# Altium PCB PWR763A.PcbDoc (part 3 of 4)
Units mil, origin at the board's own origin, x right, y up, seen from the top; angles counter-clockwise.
Board outline 5000 x 7000 mil, 4 copper layers (Top Layer, Signal Layer 1, Signal Layer 2, Bottom Layer), stack 61.2 mil thick; 559 components, 281 nets, 1477 pads, 685 vias.

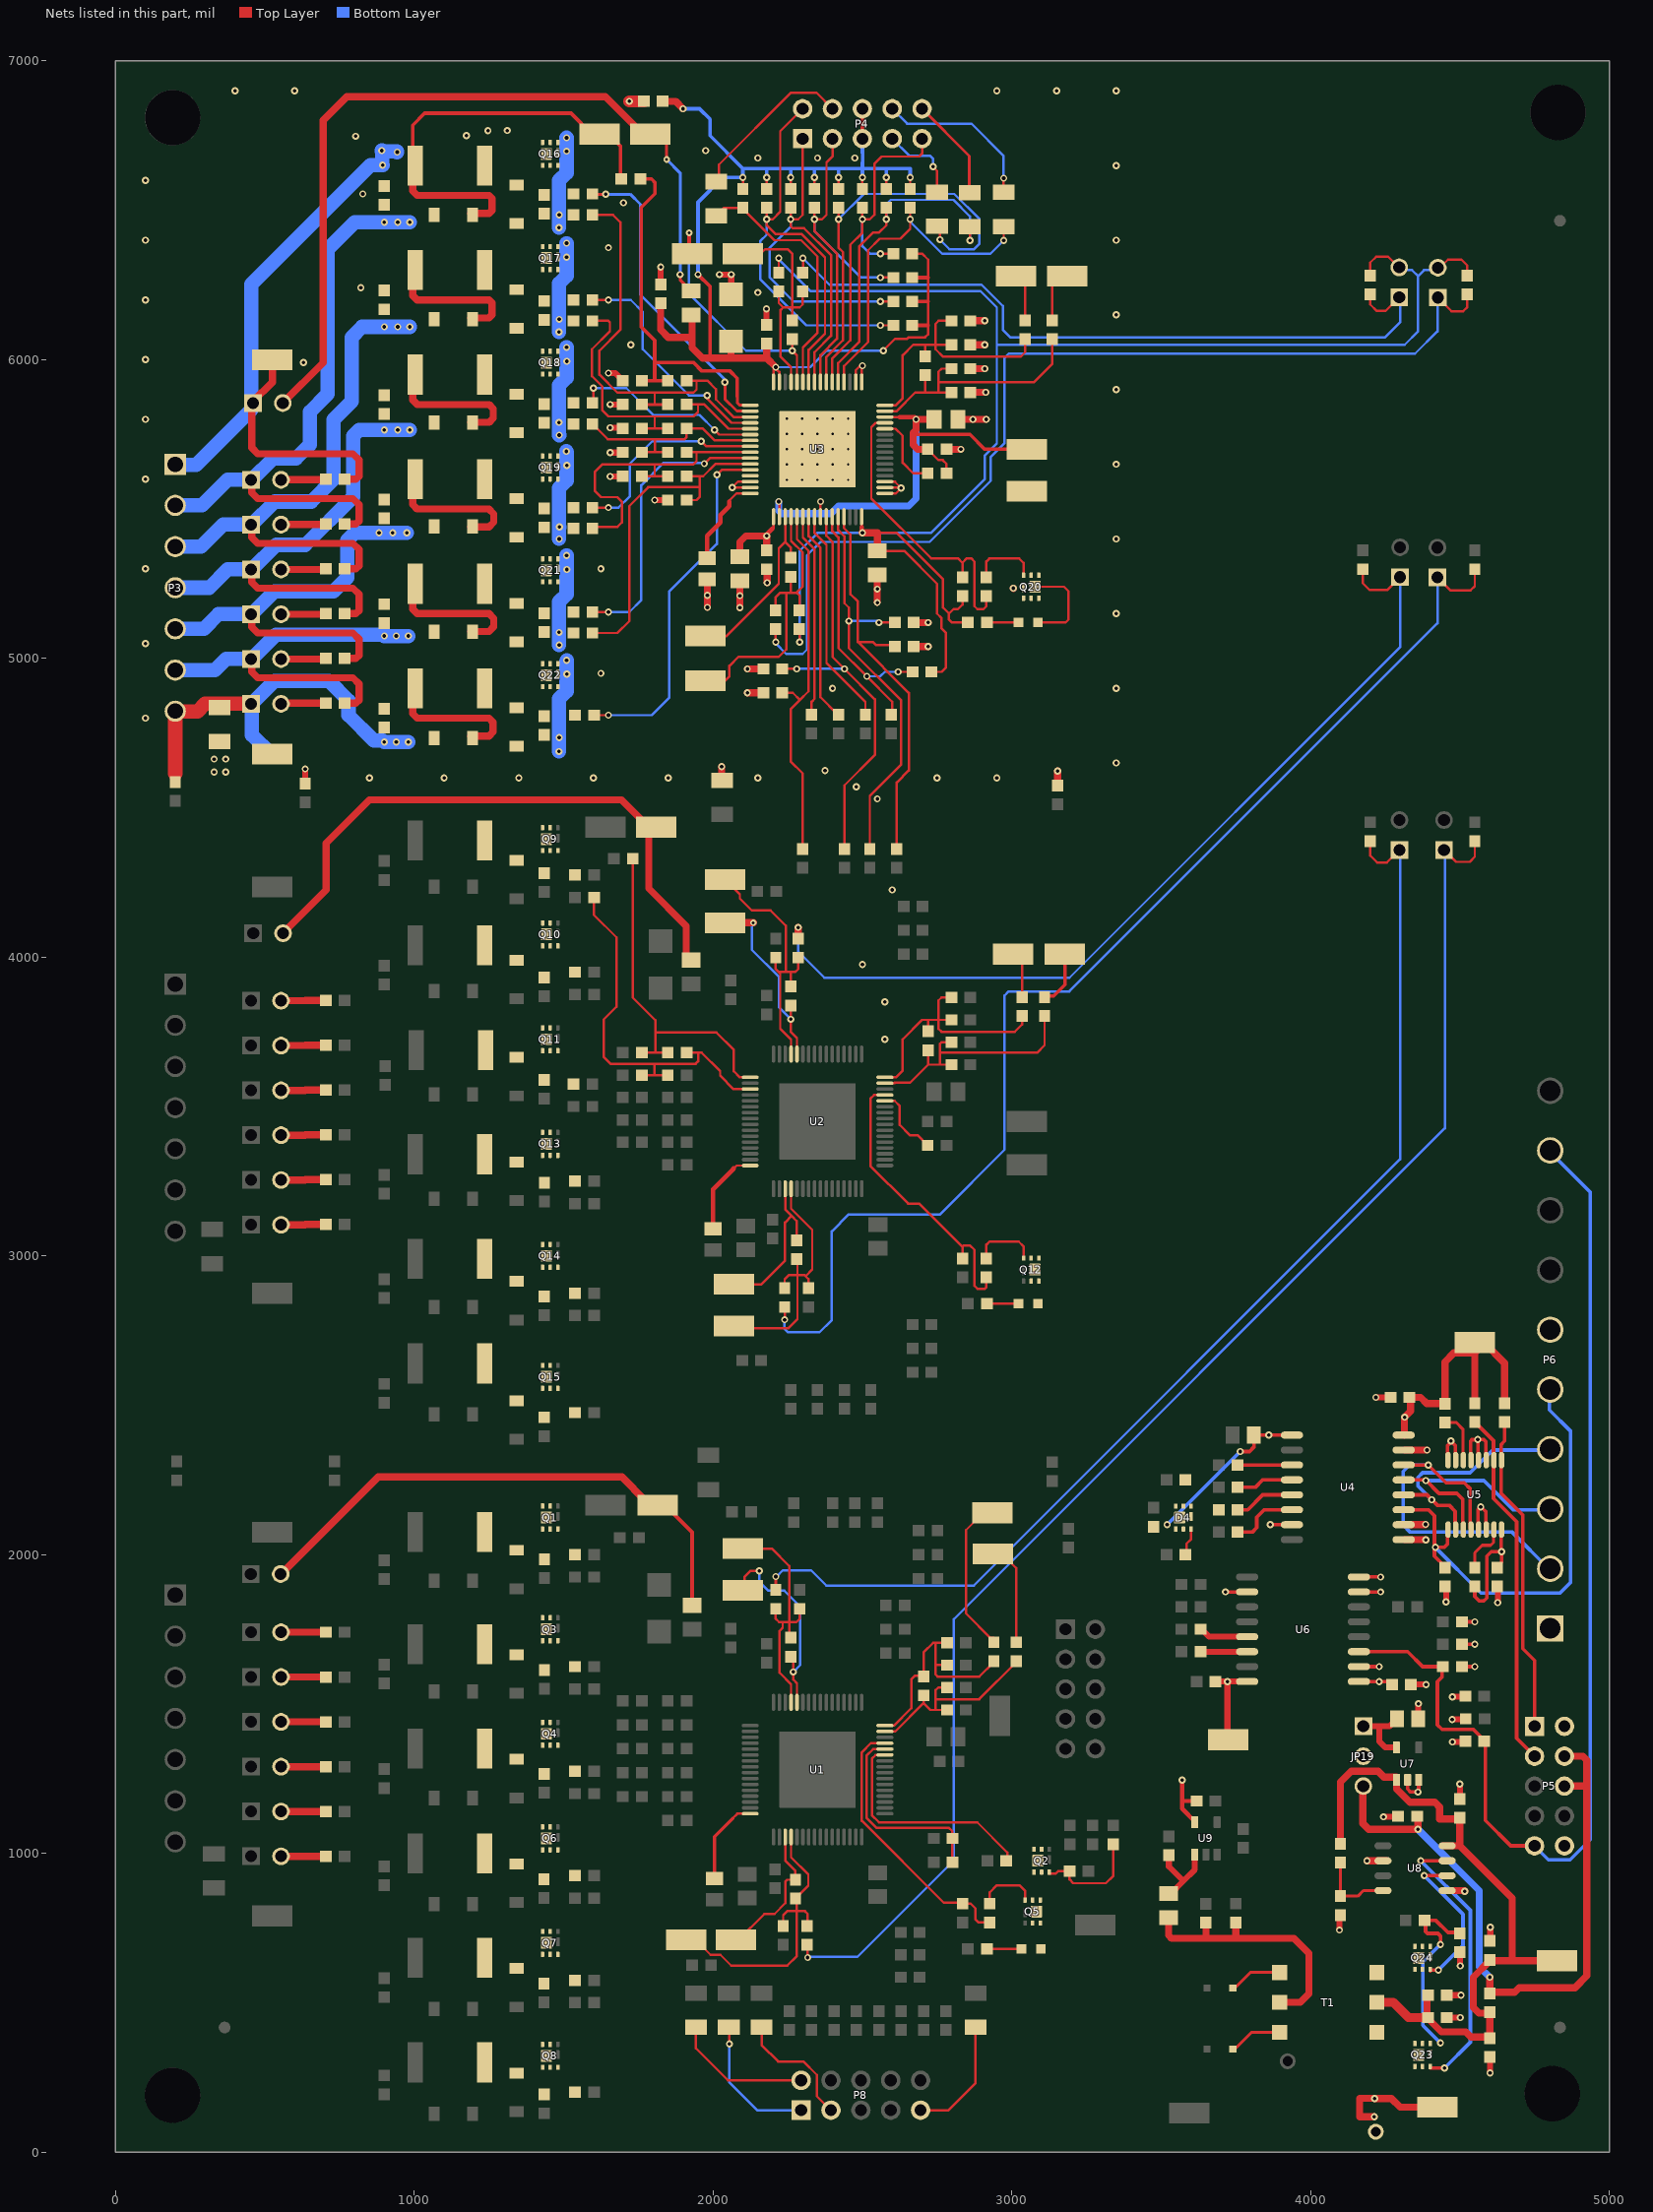
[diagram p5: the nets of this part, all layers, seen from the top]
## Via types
v1: diameter 24, hole 12, Top Layer to Bottom Layer, tented both sides, 607 vias
v2: diameter 19.68, hole 7.87, Top Layer to Bottom Layer, 75 vias
v3: diameter 22, hole 10, Top Layer to Bottom Layer, tented both sides, 3 vias

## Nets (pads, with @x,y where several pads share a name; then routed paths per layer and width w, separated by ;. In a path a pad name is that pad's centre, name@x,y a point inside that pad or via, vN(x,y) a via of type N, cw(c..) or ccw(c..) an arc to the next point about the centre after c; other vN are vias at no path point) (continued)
2-VC5: C49.2 C52.1 C53.1 R118.1 U2.3 | length 1338.8
  Top Layer w8: R118.1@1601.5,4200 1601.5,4141.5 1677,4066 1677,3834.04 1634,3791.04 1634,3666 1656.79,3643.21 1804,3643.21 ; C52.1@1761.5,3605 1803,3605 ; C53.1@1848.5,3605 1803,3605 ; C49.2@1911.5,3680 1950.22,3680 ; U2.3@2124.61,3558.27 2068.91,3558.27 2023.94,3603.24 2023.94,3618.28 1962.22,3680 1950.22,3680 ; 1803,3605 1804,3606 1804,3643.21 ; 1804,3643.21 1942.17,3643.21 1950.22,3651.26 1950.22,3680
2-VC6: C48.1 C49.1 R114.1 U2.1 | length 1190.1
  Top Layer w8: R114.1@1731.5,4330 1731.5,3864.5 1807,3789 1807,3746.91 ; C48.1@1761.5,3680 1807,3680 ; C49.1@1848.5,3680 1807,3680 ; U2.1@2124.61,3597.64 2090.36,3597.64 2070,3618 2070,3689 2011.1,3747.9 1807.99,3747.9 1807,3746.91 ; 1807,3680 1807,3746.91
3-ALERT_N: C2.2 P4.1 R4.1 U3.57 | length 1646
  Top Layer w8: R4.1@2260,6505 v1(2260,6470) ; P4.1@2300,6740 2300,6485 2285,6470 v1(2260,6470) ; U3.57@2340.16,5928.35 2340.16,5969.84 2340,5970 2340,6025 2395,6080 2395,6350 2305,6440 2267,6440 2260,6447 v1(2260,6470) ; v1(2560,6195) C2.2@2600,6195
  Bottom Layer w8: v1(2260,6470) 2260,6445 2190,6375 2190,6275 2270,6195 v1(2560,6195)
3-ALERT_S: R21.2 U3.23 | length 700.8
  Top Layer w8: U3.23@2320.47,5471.65 2320.47,5409.53 2360,5370 2360,4870 2415,4815 R21.2@2420,4815
3-CB1: R186.1 U3.12 | length 1207.1
  Top Layer w8: R186.1@1601.5,4810 v1(1650,4810) ; v1(2013,5615) 2029.1,5631.1 U3.12@2124.61,5631.1
  Bottom Layer w8: v1(1650,4810) 1795,4810 1853,4868 1853,5223 2013,5383 v1(2013,5615)
3-CB2: R178.1 U3.10 | length 967.4
  Top Layer w8: R178.1@1596.5,5155 v1(1650,5155) ; v1(1971,5652) 1989.47,5670.47 U3.10@2124.61,5670.47
  Bottom Layer w8: v1(1650,5155) 1720,5155 1760,5195 1760,5580 1835,5655 v1@1970,5655
3-CB3: R173.1 U3.8 | length 691
  Top Layer w8: R173.1@1596.5,5505 v1(1650,5505) ; v1(1961,5727) 1978.16,5709.84 U3.8@2124.61,5709.84
  Bottom Layer w8: v1(1650,5505) 1684,5505 1721,5542 1721,5651 1797,5727 v1(1961,5727)
3-CB4: R162.1 U3.6 | length 640.6
  Top Layer w8: R162.1@1596.5,5855 1600,5858.5 v1(1600,5905) ; v1(2005,5765) 2020.79,5749.21 U3.6@2124.61,5749.21
  Bottom Layer w8: v1(1600,5905) 1710,5905 1800,5815 1955,5815 v1(2005,5765)
3-CB5: R157.1 U3.4 | length 770.6
  Top Layer w8: R157.1@1600,6200 v1(1650,6200) ; v1(1980,5880) 1980,5871 2062.42,5788.58 U3.4@2121.65,5788.58
  Bottom Layer w8: v1(1650,6200) 1725,6200 1765,6160 1765,6035 1920,5880 v1(1980,5880)
3-CB6: R153.1 U3.2 | length 1045.4
  Top Layer w10: R153.1@1596.5,6555 1597.5,6554 v1(1641,6554) ; v1(2040,5925) 2040,5868 2080.05,5827.95 U3.2@2124.61,5827.95
  Bottom Layer w10: v1(1641,6554) 1723,6554 1757,6520 1757,6217 2040,5934 v1(2040,5925)
3-CELL1: C103.2 C113.1 JP5.1 P3.6 Q21.4 Q21.7 R18.2 R180.1 R182.2 R183.2 Z36.2 Z37.2 Z38.1 | length 2142.3
  Top Layer w24: JP5.1@456,4998 456,4955 476,4935 795,4935 815,4915 815,4860 805,4850 R18.2@770,4850 ; R183.2@995,4900 995,4815 1010,4800 1250,4800 1263.94,4786.06 1263.94,4753.94 1250,4740 Z38.1@1189.5,4740
  Bottom Layer w48: P3.6@200,4961.02 333.02,4961.02 370,4998 456,4998 537,5079 896,5079 v1(900,5075) v1(940,5075) v1(980,5075) ; v1(1485,5045) 1485,5085 v1(1484.88,5087.01) 1485,5087.01 1485,5190 1510,5215 1510,5297.49 v1(1510.31,5297.49) 1510,5305 v1(1510,5345)
3-CELL2: C100.2 C103.1 JP4.1 P3.5 Q19.4 Q19.7 R17.2 R174.1 R175.2 R176.2 Z34.2 Z35.2 Z36.1 | length 2292.6
  Top Layer w8: v1(1509.17,5693.1) 1509.57,5691.11 1509.77,5691.15 v1@1510,5690
  Top Layer w24: JP4.1@456,5148 456,5105 476,5085 795,5085 815,5065 815,5010 805,5000 R17.2@770,5000 ; R176.2@995,5250 995,5165 1010,5150 1250,5150 1265.73,5134.27 1265.73,5105.73 1250,5090 Z36.1@1189.5,5090
  Bottom Layer w48: P3.5@200,5098.81 295.82,5098.82 345,5148 456,5148 532,5224 730,5224 776,5270 776,5395 801,5420 v1(882,5420) v1(928,5420) v1(975,5420) ; v1(1485,5400) 1485,5435 v1(1486,5440) 1485,5440 1485,5570 1510,5595 1510,5646.51 v1(1510.58,5646.51) 1510,5651 1510,5690 1509.77,5691.15 1509.57,5691.11 v1(1509.17,5693.1)
3-CELL3: C95.2 C100.1 JP3.1 P3.4 Q18.4 Q18.7 R16.2 R163.1 R164.2 R167.2 Z32.2 Z33.2 Z34.1 | length 2432.5
  Top Layer w24: JP3.1@456,5298 456,5255 476,5235 795,5235 815,5215 815,5160 805,5150 R16.2@770,5150 ; R167.2@995,5600 995,5515 1010,5500 1250,5500 1266.09,5483.91 1266.09,5456.09 1250,5440 Z34.1@1189.5,5440
  Bottom Layer w48: P3.4@200,5236.61 313.61,5236.61 375,5298 456,5298 538,5380 635,5380 795,5540 795,5745 815,5765 v1(900,5765) v1(945,5765) v1(985,5765) ; v1(1485.17,5747.45) 1485,5750 1485,5785 v1(1484,5790) 1485,5790 1485,5915 1510,5940 1510,5994.7 v1(1510.65,5994.7) 1510,6000 1510,6040 v1(1509.91,6041.1)
3-CELL4: C92.2 C95.1 JP2.1 P3.3 Q17.4 Q17.7 R15.2 R158.1 R159.2 R160.2 Z30.2 Z31.2 Z32.1 | length 2642.7
  Top Layer w24: JP2.1@456,5448 456,5405 476,5385 795,5385 815,5365 815,5310 805,5300 R15.2@770,5300 ; R160.2@995,5950 995,5865 1010,5850 1250,5850 1264.66,5835.34 1264.66,5804.66 1250,5790 Z32.1@1189.5,5790
  Bottom Layer w48: P3.3@200,5374.41 286.41,5374.41 360,5448 456,5448 533,5525 655,5525 730,5600 730,5800 790,5860 790,6075 825,6110 v1(900,6110) v1(945,6110) v1(985,6110) ; v1(1484.47,6092.3) 1485,6095 v1(1485,6135) 1485,6255 1510,6280 1510,6342.93 v1(1509.8,6342.93) 1510,6350 v1(1510,6390)
3-CELL5: C89.2 C92.1 JP1.1 P3.2 Q16.4 Q16.7 R14.2 R154.1 R155.2 R156.2 Z28.2 Z29.2 Z30.1 | length 2835.3
  Top Layer w24: JP1.1@456,5598 456,5555 476,5535 795,5535 815,5515 815,5460 805,5450 R14.2@770,5450 ; R156.2@995,6300 995,6215 1010,6200 1250,6200 1260,6190 1260,6150 1250,6140 Z30.1@1189.5,6140
  Bottom Layer w48: P3.2@200,5512.2 200.8,5513 290,5513 375,5598 456,5598 528,5670 605,5670 650,5715 650,5825 710,5885 710,6370 800,6460 v1(900,6460) v1(945,6460) v1(985,6460) ; v1(1484.6,6441.83) 1485,6445 v1(1485,6485) 1485,6600 1510,6625 1510,6697.97 v1(1509.87,6697.97) 1510,6700 1510,6740 v1(1510.04,6742.79)
3-CELL6: C89.1 J7.1 P3.1 R13.2 R150.2 R151.2 TP1.1 TP-C5.1 Z28.1 | length 3734.5
  Top Layer w12: R150.2@995,6650 995,6785 1035,6825 1525,6825 1595,6755 1650,6755 1690,6715 R151.2@1690,6608.5
  Top Layer w24: J7.1@455,5850 456,5850 456,5705 476,5685 795,5685 815,5665 815,5610 805,5600 R13.2@770,5600 ; J7.1@460,5855 460,5860 525,5925 TP1.1@525,6000 ; R150.2@995,6650 995,6565 1010,6550 1250,6550 1260,6540 1260,6500 1250,6490 Z28.1@1189.5,6490
  Bottom Layer w48: P3.1@200,5650 202,5648 270,5648 455,5833 455,6252 854,6651 v1@892.5,6651 ; v1(894,6651) v1@892.5,6651 ; v1(943,6695) 943,6697.5 v1@892.5,6697.5 ; v1@892.5,6651 v1@892.5,6697.5 ; v1@892.5,6697.5 892.5,6700 v1(891,6700) 891,6697.5 v1@892.5,6697.5
3-CONV_N: R1.1 R2.1 U3.59 | length 853.3
  Top Layer w8: R1.1@2011,6481.91 2037.59,6508.5 R2.1@2100,6508.5 ; R2.1@2100,6505 2205,6400 2295,6400 2350,6345 2350,6090 2300.79,6040.79 U3.59@2300.79,5928.35
3-CONV_S: C111.1 R25.2 U3.21 | length 1233.6
  Top Layer w8: C111.1@2231.5,4885 2267,4885 2291,4861 ; U3.21@2281.1,5471.65 2281.1,5398.9 2320,5360 2320,4890 2291,4861 ; R25.2@2300,4365 2300,4615.17 2260,4655.17 2260,4830 2291,4861
3-CS_N: R9.1 R12.1 U3.52 | length 1146.9
  Top Layer w8: U3.52@2438.58,5928.35 2438.58,5978.58 2519,6059 2519,6366 2558,6405 2627,6405 2660,6438 v1(2660,6470) R9.1@2660,6505 ; R12.1@2958.87,6446.72 2973.24,6432.35 v1(2973.24,6399.38)
  Bottom Layer w8: v1(2660,6470) 2660,6462 2768,6354 2927.86,6354 v1(2973.24,6399.38)
3-CS_S: C110.1 R28.2 U3.29 | length 1339.5
  Top Layer w8: U3.29@2438.58,5471.65 2438.58,5436.42 2460,5415 2460,5215 2485,5190 2485,5055 ; C110.1@2605,5040 2600,5045 2545,5045 2535,5055 2485,5055 ; R28.2@2615,4365 2615,4584.43 2655.57,4625 2655.57,4884.43 2485,5055
3-DRDY_N: C1.2 P4.2 R3.1 U3.58 | length 1877.6
  Top Layer w8: R3.1@2180,6505 v1(2180,6470) ; P4.2@2300,6840 2225,6765 2225,6495 2200,6470 v1(2180,6470) ; U3.58@2320.47,5928.35 2320.47,6032.97 2375,6087.5 2375,6342.63 2297.63,6420 2210,6420 2180,6450 v1(2180,6470) ; v1(2560,6115) C1.2@2600,6115
  Bottom Layer w8: v1(2180,6470) 2180,6418.81 2159,6397.81 2159,6268.37 2312.37,6115 v1(2560,6115)
3-DRDY_S: R24.2 U3.22 | length 677
  Top Layer w8: U3.22@2300.79,5471.65 2300.79,5404.21 2340,5365 2340,4865 2330,4855 R24.2@2330,4815
3-FAULT_N: C3.2 P4.3 R5.1 U3.56 | length 1304.3
  Top Layer w8: R5.1@2340,6505 v1(2340,6470) ; U3.56@2359.84,5928.35 2359.84,6014.84 2415,6070 2415,6355 2340,6430 v1(2340,6470) ; P4.3@2400,6740 2400,6680 2380,6660 2380,6485 2365,6470 v1(2340,6470) ; v1(2560,6275) C3.2@2600,6275
  Bottom Layer w8: v1(2340,6470) 2340,6430 2495,6275 v1(2560,6275)
3-FAULT_S: R22.2 U3.24 | length 727
  Top Layer w8: U3.24@2340.16,5471.65 2340.16,5419.84 2380,5380 2380,4985 2510,4855 R22.2@2510,4815
3-LDOA: C116.1 C117.1 U3.17 | length 260.9
  Top Layer w8: 2202.36,5437.36 U3.17@2202.36,5471.65
  Top Layer w15: v1(2180,5410) 2180,5415 2200,5435
  Top Layer w24: C117.1@2090,5340 2090,5390 2110,5410 v1(2180,5410) C116.1@2180,5365
3-LDOD1: C118.1 C119.1 R172.2 TP-VPROG3.1 U3.18 U3.46 | length 1655.8
  Top Layer w8: v1(2220,5525) 2222.05,5522.95 U3.18@2222.05,5471.65 ; U3.46@2578.35,5808.27 2625,5808.27 ; C118.1@2718.5,5700 2754.85,5663.65 2768.96,5663.65 2781.5,5651.11 R172.2@2781.5,5620
  Top Layer w12: 2670,5750 2860,5750 2910,5700 TP-VPROG3.1@3050,5700
  Top Layer w15: 2625,5808.27 2675,5808.27 v1(2680,5800)
  Top Layer w24: C118.1@2715,5700 2685,5700 2670,5715 2670,5750 2670,5755 2680,5765 v1(2680,5800) C119.1@2740,5800
  Bottom Layer w24: v1(2220,5525) 2220,5495 2230,5485 2395,5485 2420,5510 2655,5510 2680,5535 v1(2680,5800)
3-REG50: C96.1 C97.1 C115.1 J8.2 J9.2 R161.2 R168.2 R177.1 RT5.2 RT6.2 U3.32 | length 5938.3
  Top Layer w8: C97.1@2220,6291.5 v1(2220,6340) ; v1(2290,5055) C96.1@2290,5095 ; 2497.64,5440 U3.32@2497.64,5471.65 ; C115.1@2550,5360 2640,5360 2750,5250 2750,5150 2765,5135 2765,5100 2780,5085 2780,4970 2765,4955 R177.1@2735,4955 ; 2550,5420 2615,5420 2770,5265 2770,5170 2790,5150 ; R168.2@2835,5205 2835,5180 2820,5165 2805,5165 2790,5150 ; R161.2@2850,5120 2800,5120 2790,5130 2790,5150 ; RT6.2@4200,6270 4200,6325 4220,6345 4260,6345 4300,6305 J9.2@4300,6300 ; J8.2@4425,6300 4460,6335 4505,6335 4525,6315 RT5.2@4525,6270
  Top Layer w15: 2497.64,5440 2497.64,5422.36 v1(2500,5420)
  Top Layer w25: v1(2500,5420) 2550,5420 C115.1@2550,5360
  Bottom Layer w8: v1(2220,6340) 2220,6336 2326,6230 2895,6230 2950,6175 2950,6050 ; v1(2290,5055) 2290,5360 2350,5420 2728.94,5420 2910,5601.06 2910,5680 2950,5720 2950,6050 ; J9.2@4300,6300 4340,6300 4360,6280 ; J8.2@4425,6300 4380,6300 4360,6280 ; 2950,6050 4315,6050 4360,6095 4360,6280
3-SCLK_N: R6.1 R10.1 U3.55 | length 1435.9
  Top Layer w8: U3.55@2379.53,5925.39 2379.53,6009.53 2435,6065 2435,6360 2420,6375 v1(2420,6470) R6.1@2420,6505 ; R10.1@2750,6446.91 2760,6436.91 v1(2760,6402)
  Bottom Layer w8: v1(2420,6470) 2505,6555 2807.63,6555 2892,6470.63 2892,6388 2874,6370 2791,6370 2760,6401 v1(2760,6402)
3-SCLK_S: C108.1 R26.2 U3.26 | length 1421.2
  Top Layer w8: C108.1@2235,4965 v1(2280,4965) ; U3.26@2379.53,5471.65 2379.53,5410.47 2400,5390 2400,5005 v1(2440,4965) 2542,4863 2542,4677 2440,4575 R26.2@2440,4365
  Bottom Layer w8: v1(2280,4965) v1(2440,4965)
3-SDI_N: R8.1 R11.1 U3.53 | length 1141.6
  Top Layer w8: U3.53@2418.9,5928.35 2418.9,5988.9 2490,6060 2490,6380 2535,6425 2555,6425 2580,6450 v1(2580,6470) R8.1@2580,6505 ; v1(2860,6399) R11.1@2860,6445.54
  Bottom Layer w8: v1(2580,6470) 2580,6520 2595,6535 2805,6535 2860,6480 v1(2860,6399)
3-SDI_S: C109.1 R27.2 U3.28 | length 1389.7
  Top Layer w8: U3.28@2418.9,5471.65 2418.9,5429.36 2440,5408.26 2440,5185 2455,5170 v1(2455,5125) 2455,5033.94 2630,4858.94 2630,4645 2525,4540 R27.2@2525,4365 ; v1(2555,5120) C109.1@2605,5120
  Bottom Layer w8: v1(2455,5125) 2550,5125 v1(2555,5120)
3-SDO_N: C5.2 P4.9 R7.1 U3.54 | length 1259.5
  Top Layer w8: U3.54@2399.21,5928.35 2399.21,6004.21 2460,6065 2460,6385 2500,6425 v1(2500,6470) ; R7.1@2500,6505 v1(2500,6470) ; v1(2560,6355) C5.2@2600,6355 ; P4.9@2700,6740 2700,6690 2690,6680 2565,6680 2540,6655 2540,6485 2525,6470 v1(2500,6470)
  Bottom Layer w8: v1(2500,6470) 2500,6380 2525,6355 v1(2560,6355)
3-SDO_S: R23.2 R177.2 U3.27 | length 896
  Top Layer w8: U3.27@2399.21,5471.65 2399.21,5425.79 2420,5405 2420,5035 v1(2515,4940) 2600,4855 R23.2@2600,4815 ; v1(2620,4955) R177.2@2665,4955
  Bottom Layer w8: v1(2515,4940) 2560,4940 2575,4955 v1(2620,4955)
3-VBAT: C1.1 C2.1 C3.1 C4.1 C5.1 C88.1 C114.1 P4.5 P4.6 R2.2 R3.2 R4.2 R5.2 R6.2 R7.2 R8.2 R9.2 R152.2 U3.63 U3.64 Z27.2 | length 4241.1
  Top Layer w8: R2.2@2100,6575 v1(2100,6610) ; R3.2@2180,6575 v1(2180,6610) ; U3.64@2202.36,5928.35 2202.36,5967.36 v1@2207.91,5972.91 ; v1(2210,5975) v1@2207.91,5972.91 ; U3.63@2222.05,5928.35 2222.05,5958.76 v1@2207.91,5972.91 ; R4.2@2260,6575 v1(2260,6610) ; R5.2@2340,6575 v1(2340,6610) ; R6.2@2420,6575 v1(2420,6610) ; R7.2@2500,6575 v1(2500,6610) ; v1(2570,6030) 2610,6070 2650,6070 2655,6075 2710,6075 2720,6085 2720,6115 2720,6195 2720,6275 2720,6335 2700,6355 C5.1@2670,6355 ; R8.2@2580,6575 v1(2580,6610) ; R9.2@2660,6575 v1(2660,6610)
  Top Layer w12: v1(1950,6285) 1990,6245 1990,6005 ; P4.5@2500,6740 P4.6@2500,6840 ; C1.1@2670,6115 2720,6115 ; C2.1@2670,6195 2720,6195 ; C3.1@2670,6275 2720,6275
  Top Layer w24: C114.1@1825,6185 1825,6100 1850,6075 1930,6075 ; C88.1@1835,6865 1875,6865 v1(1900,6840) ; R152.2@1930,6155 1930,6075 ; Z27.2@2060,6070.5 2060,6005 ; C4.1@2180,6050 2180,6005 ; v1(2210,5975) 2180,6005 ; 1930,6075 1930,6040 1965,6005 1990,6005 2060,6005 ; 2060,6005 2180,6005
  Bottom Layer w8: v1(2210,5975) 2325,5975 2380,6030 v1(2570,6030)
  Bottom Layer w12: v1(1900,6840) 1955,6840 1990,6805 1990,6750 2100,6640 ; v1(1950,6285) 1950,6527.09 2032.91,6610 v1(2100,6610) 2100,6640 ; v1(2180,6610) 2180,6640 ; v1(2260,6610) 2260,6640 ; v1(2340,6610) 2340,6640 ; v1(2420,6610) 2420,6640 ; v1(2500,6610) 2500,6640 ; P4.5@2500,6740 2500,6692.13 2501,6691.13 2501,6660.62 2500,6659.62 2500,6640 ; v1(2580,6610) 2580,6640 ; v1(2660,6610) 2660,6640 2580,6640 ; 2100,6640 2180,6640 ; 2180,6640 2260,6640 ; 2260,6640 2340,6640 ; 2340,6640 2420,6640 ; 2420,6640 2500,6640 ; 2500,6640 2580,6640
3-VC0: C4.2 C6.2 C7.1 C86.2 C88.2 C90.2 C93.2 C98.2 C101.2 C104.2 C105.2 C107.2 C108.2 C109.2 C110.2 C111.2 C112.2 C113.2 C114.2 C115.2 C116.2 C117.2 C118.2 C119.2 JP6.1 P3.7 Q20.4 Q20.7 Q22.4 Q22.7 R19.1 R19.2 R20.2 R29.2 R181.2 R185.2 R187.1 TP2.1 TP-VSS2.1 U3.13 U3.14 U3.15 U3.25 U3.33 U3.34 U3.35 U3.49 U3.50 U3.65 Z27.1 Z38.2 Z39.2 | length 3647.8
  Top Layer w8: v1(2064,5572) v1(2064,5572) ; U3.15@2121.65,5572.05 v1(2064,5572) ; U3.14@2121.65,5591.73 2083.73,5591.73 v1(2064,5572) ; U3.25@2359.84,5471.65 2359.84,5524.84 v1(2360,5525) ; U3.50@2477.95,5928.35 2477.95,5965 2492.95,5980 v1(2500,5980) 2497.64,5977.64 U3.49@2497.64,5928.35 ; U3.33@2578.35,5552.36 2612.36,5552.36 v1(2630,5570) v1@2627.95,5572.05 ; U3.34@2578.35,5572.05 v1@2627.95,5572.05 ; U3.35@2578.35,5591.73 2610,5591.73 2610,5590 v1@2627.95,5572.05
  Top Layer w20: R20.2@200,4590 200,4615 ; C6.2@635,4581.5 v1(635,4630) ; v1(1650,5955) 1673.5,5955 C86.2@1698.5,5930 ; v1(1656,5609) C101.2@1698.5,5609 ; v1(1656,5689) C98.2@1698.5,5689 ; v1(1656,5772) C93.2@1698.5,5772 ; v1(1656,5850) C90.2@1698.5,5850 ; v1(1805,5530) C107.2@1848.5,5530 ; C114.2@1825,6251.5 v1(1825,6310) ; v1(2022,6285) v1(2061,6285) 2061,6219.74 Z27.1@2060,6218.74 ; v1(2179,6170) 2179,6117.5 C4.2@2180,6116.5
  Top Layer w24: v1(1981,5171) v1(1981,5211) C112.2@1981,5261 ; R29.2@2029,4593 v1(2029,4638) ; v1(2090,5170) v1(2090,5210) C117.2@2090,5260 ; v1(2115,4885) C111.2@2165,4885 ; v1(2115,4965) C108.2@2165,4965 ; v1(2181,5253) C116.2@2181,5298 ; v1(2550,5187) v1(2550,5232) C115.2@2550,5277 ; C110.2@2675,5040 v1(2720,5040) ; C109.2@2675,5120 v1(2720,5120) ; C118.2@2785,5700 v1(2830,5700) ; C119.2@2820,5800 v1(2870,5800) v1(2915,5800) ; R185.2@2865,5970 v1(2910,5970) ; R181.2@2865,6050 v1(2910,6050) ; C105.2@2865,6131 v1(2910,6131) ; C104.2@2868,5891 v1(2913,5891) ; v1(3005,5235) v1@3005.91,5234.09 ; C7.1@3154,4578 v1(3154,4623)
  Top Layer w40: v1(1720,6865) C88.2@1768.5,6865
  Top Layer w48: 200,4615 P3.7@200,4823 ; P3.7@200,4823.22 P3.7@200,4823 ; JP6.1@456,4848 350,4848 300,4848 275,4823 P3.7@200,4823
  Bottom Layer w48: 520,4680 456,4744 456,4848 532,4924 715,4924 780,4859 780,4810 865,4725 895,4725 v1(900,4720) v1(940,4720) v1(980,4720) ; v1(1484.22,4688.31) 1485,4695 v1(1485,4735) 1485,4865 1510,4890 1510,4947.07 v1(1510.48,4947.07) 1510,4950 1510,4990 v1(1510.07,4994.07)
  other v1: 2575,3725 2575,3850 2500,3975 2600,4225 2550,4530 2480,4570 850,4600 1100,4600 1350,4600 1600,4600 1850,4600 2150,4600 2750,4600 2950,4600 330,4620 369,4620 2375,4625 3350,4650 330,4663 369,4663 100,4800 2400,4900 3350,4900 1625,4950 100,5050 3350,5150 100,5300 1625,5300 3350,5400 100,5600 3350,5650 100,5800 3350,5900 629,5991 100,6000 1725,6050 3350,6150 100,6200 2150,6225 821,6241 1650,6375 100,6400 3350,6400 1700,6525 828,6555 100,6600 3350,6650 2150,6675 2350,6675 2475,6675 1975,6700 804,6748 1175,6750 1246.62,6766.94 1311.64,6767.13 400,6900 600,6900 2950,6900 3150,6900 3350,6900
  other v2: 2247.64,5597.64 2298.82,5597.64 2350,5597.64 2401.18,5597.64 2452.36,5597.64 2247.64,5648.82 2298.82,5648.82 2350,5648.82 2401.18,5648.82 2452.36,5648.82 2247.64,5700 2298.82,5700 2350,5700 2401.18,5700 2452.36,5700 2247.64,5751.18 2298.82,5751.18 2350,5751.18 2401.18,5751.18 2452.36,5751.18 2247.64,5802.36 2298.82,5802.36 2350,5802.36 2401.18,5802.36 2452.36,5802.36
3-VC1: C102.2 C107.1 R182.1 U3.11 | length 1133.8
  Top Layer w8: R182.1@1596.5,5085 1680,5085 1720,5125 1720,5510 1783,5573 1955,5573 ; C107.1@1911.5,5530 1945,5530 1955,5540 1955,5573 ; C102.2@1911.5,5610 1955,5610 ; U3.11@2124.61,5650.79 2007.79,5650.79 1967,5610 1955,5610 ; 1955,5573 1955,5610
3-VC2: C99.2 C101.1 C102.1 R175.1 U3.9 | length 1046.9
  Top Layer w8: R175.1@1605,5440 1680,5440 1695,5455 1695,5525 1680,5540 1625,5540 1605,5560 1605,5625 1630,5650 1805,5650 ; C101.1@1765,5610 1805,5610 ; C102.1@1845,5610 1805,5610 ; C99.2@1915.16,5690.16 1945,5690.16 ; U3.9@2121.65,5690.16 1945,5690.16 ; 1805,5610 1805,5650 ; 1805,5650 1935,5650 1945,5660 1945,5690.16
3-VC3: C94.2 C98.1 C99.1 R164.1 U3.7 | length 729.6
  Top Layer w8: R164.1@1596.5,5785 1647.5,5734 1806,5734 ; C98.1@1761.5,5690 1807,5690 ; C99.1@1848.5,5690 1807,5690 ; U3.7@2124.61,5729.53 2005.47,5729.53 1965,5770 C94.2@1911.5,5770 1911.5,5740.5 1905,5734 1806,5734 ; 1806,5734 1806,5691 1807,5690
3-VC4: C91.2 C93.1 C94.1 R159.1 U3.5 | length 1117.6
  Top Layer w8: R159.1@1600,6130 1650,6130 1655,6125 1655,6095 1595,6035 1595,5945 1630,5910 1630,5830 1650,5810 1805,5810 ; C93.1@1765,5770 1805,5770 ; C94.1@1845,5770 1805,5770 ; C91.2@1911.5,5850 1971,5850 2052.1,5768.9 U3.5@2124.61,5768.9 ; 1950,5850 1950,5825 1935,5810 1805,5810 ; 1805,5770 1805,5810
3-VC5: C87.2 C90.1 C91.1 R155.1 U3.3 | length 1430.3
  Top Layer w8: R155.1@1600,6485 1665,6485 1690,6460 1690,6100 1620,6030 1620,5950 1680,5890 1805,5890 ; 1805,5850 1805,5890 ; C87.2@1915,5930 1945,5930 ; U3.3@2124.61,5808.27 2068.73,5808.27 2010,5867 2010,5901 1981,5930 1945,5930 ; 1805,5890 1935,5890 1945,5900 1945,5930
  Top Layer w10: C90.1@1761.5,5850 C91.1@1848.5,5850
3-VC6: C86.1 C87.1 R151.1 U3.1 | length 1269.3
  Top Layer w10: 2081,5877 2081,5856 2089,5848 2124.24,5848 U3.1@2124.61,5847.64
  Top Layer w12: R151.1@1756.5,6605 1794,6605 1806,6593 1806,6556 1760,6510 1760,6110 1805,6065 1805,5991 ; C86.1@1761.5,5930 1805,5930 ; C87.1@1848.5,5930 1805,5930 ; 2081,5877 2081,5938.22 2057.22,5962 1963,5962 1934,5991 1805,5991 ; 1805,5930 1805,5991
3.3_SW: C121.1 C122.1 C124.1 JP19.2 P6.1 R190.2 R191.2 R192.2 R195.2 R198.2 R199.2 R200.2 TP-19.1 U4.10 U4.16 U5.16 U6.1 U6.7 | length 1739.7
  Top Layer w12: U6.1@4164.4,1575.1 4229.9,1575.1 v1(4230,1575) 4270,1575 C121.1@4270,1565 ; U6.7@4164.4,1875.1 4234.9,1875.1 v1(4235,1875) ; R198.2@4510,1625 v1(4550,1625) ; R199.2@4510,1700 v1(4550,1700) ; R200.2@4510,1775 v1(4550,1775) ; R195.2@4550,1890 4550,1860 4565,1845 4580,1845 4590,1855 4590,1995 4605,2010 v1(4640,2010) ; C122.1@4625,1960 4640,1975 v1(4640,2010) ; U5.16@4638,2088.3 4638,2012 v1(4640,2010)
  Top Layer w24: U4.10@4314.6,2099.9 4385,2099.9 v1(4385,2101) ; U4.16@4314.6,2399.9 4314.6,2459.6 v1(4315,2460) 4315,2460.36 4335,2480.36 C124.1@4335,2525 ; C124.1@4331.5,2526 4369,2526 4389.5,2505.5 R190.2@4450,2505.5 ; R190.2@4450,2510 4450,2645 4480,2675 4545.55,2675 4547.47,2673.08 ; R192.2@4550,2506.5 4550,2670.55 4547.47,2673.08 ; R191.2@4650,2510 4650,2641.09 4582.74,2708.35 4547.47,2673.08
5V_USB: C125.1 JP19.3 P5.4 P5.6 R210.1 | length 2233.3
  Top Layer w24: JP19.3@4175,1225 4175,1100 4195,1080 v1(4360,1080) C125.1@4360,1125 ; v1(4600,585) 4600,535 4683.63,535 4698.63,550 4885,550 4925.04,590.04 4925.04,1225 ; P5.6@4850,1225 4925.04,1225 ; P5.4@4850,1325 4912,1325 4925.27,1311.73 4925.27,1225 4925.04,1225
  Bottom Layer w24: v1(4360,1080) 4565,875 4565,620 v1(4600,585)
AGND: C121.2 C122.2 C124.2 C125.2 C126.2 C127.2 C128.2 C129.2 C133.2 C134.2 C136.2 C137.1 P5.2 P5.10 P6.6 R204.1 R207.1 R208.1 R209.1 R215.1 TP-AGN.1 U4.9 U4.15 U5.3 U5.4 U5.5 U5.7 U5.8 U5.13 U5.14 U6.2 U6.8 U7.2 U7.3 U8.2 U8.5 | length 2312
  Top Layer w12: U6.2@4164.4,1625.1 4229.9,1625.1 v1(4230,1625) ; U6.8@4164.4,1925.1 4234.9,1925.1 v1(4235,1925) ; U7.2@4325,1255 4325,1215 4335,1205 v1(4360,1205) 4362,1207 U7.3@4362,1255 ; U5.8@4458.8,2307.3 4458.8,2365 v1@4471.9,2378.1 ; v1(4470,2380) v1@4471.9,2378.1 ; U5.7@4484.4,2307.3 4484.4,2365.6 v1@4471.9,2378.1 ; U5.5@4535.6,2307.3 4535.6,2380 4540,2384.4 4559.4,2384.4 v1(4560,2385) ; U5.13@4561.1,2088.3 4561.1,2151.1 v1(4570,2160) 4585,2145 4586.7,2145 U5.14@4586.7,2088.3 ; U5.4@4561.2,2307.3 4561.2,2383.8 v1(4560,2385) ; U5.3@4586.8,2307.3 4586.8,2378.2 4580,2385 v1(4560,2385)
  Top Layer w20: v1(4097,743) 4097,790.5 C136.2@4100,793.5 ; v1(4219,2526) C124.2@4268.5,2526 ; v1(4244,1122) 4291.5,1122 C125.2@4293.5,1124 ; C121.2@4336.5,1565 v1(4387,1565) ; C126.2@4360.43,1450 4361,1450.57 v1(4361,1501) ; R204.1@4450,1893.5 4454,1889.5 v1(4454,1842) ; C134.2@4456.5,450 v1(4501,450) ; C133.2@4456.5,525 v1(4504,525) ; v1(4474,1448) 4517.5,1448 R208.1@4519.5,1450 ; v1(4475,1373) 4516.5,1373 R207.1@4518.5,1375 ; v1(4475,1524) 4516.5,1524 R209.1@4518.5,1526 ; R215.1@4500,668.5 4501,667.5 v1(4501,623) ; C129.2@4500,1181.5 v1(4500,1232) ; C127.2@4600,318.5 4601,317.5 v1(4601,265) ; C128.2@4600,706.5 4602,708.5 v1(4602,752) ; C122.2@4625,1893.5 4627,1891.5 v1(4627,1839)
  Top Layer w24: v1(4189.05,974.87) 4189.05,975 U8.2@4255,975 ; v1@4213.57,118.35 v1(4213.57,117.59) 4165.41,117.59 4164.5,118.5 4164.5,179.6 4214.33,179.6 v1(4214.33,178.87) 4271.13,178.87 4300,150 TP-AGN.1@4425,150 ; U4.9@4314.6,2049.9 4386,2049.9 v1(4386,2049) ; U4.15@4314.6,2349.9 4389.9,2349.9 v1(4390,2350) ; U8.5@4444,875 4516.18,875 v1(4516.18,872.98)
ALERT: P6.3 U4.13 U5.11 | length 776.6
  Top Layer w12: U4.13@4314.6,2249.9 4314.7,2250 v1@4383.75,2250 ; v1(4385.79,2247.96) v1@4383.75,2250 ; U5.11@4509.9,2088.3 4509.9,2185 4489.9,2205 4430,2205 4385,2250 v1@4383.75,2250
  Bottom Layer w12: v1(4385.79,2247.96) 4580.43,2247.96 4678.38,2150 P6.3@4800,2150
CONV: P6.5 R204.2 U4.11 U5.9 | length 1600.3
  Top Layer w12: U4.11@4314.6,2149.9 4395,2149.9 4414.9,2130 4414.9,2030 4415,2029.9 4415,2025 v1(4418,2024) ; R204.2@4450,1960 4415,1995 4415,2024 v1(4418,2024) ; U5.9@4458.7,2088.3 4458.7,2035 4448.7,2025 4418,2025 v1(4418,2024)
  Bottom Layer w12: v1(4418,2024) 4571,1871 4835,1871 4870,1906 4870,2414 4800,2484 P6.5@4800,2550
CS: P5.9 P6.9 R198.1 R207.2 U6.3 | length 3740
  Top Layer w12: U6.3@4164.4,1675.1 4164.5,1675 4325,1675 4375,1625 4440,1625 4440,1590 4425,1575 4425,1430 4440,1415 4545,1415 4585,1375 4585,1110 4670,1025 P5.9@4750,1025
  Bottom Layer w12: P5.9@4750,1025 4796.5,978.5 4869.26,978.5 4936.5,1045.74 4936.5,3213.5 P6.9@4800,3350
DRDY: P6.4 U4.12 U5.10 | length 822
  Top Layer w12: U4.12@4314.6,2199.9 4314.7,2200 4390,2200 v1@4405.9,2184.1 ; v1(4405.9,2183.59) v1@4405.9,2184.1 ; U5.10@4484.3,2088.3 4484.3,2145 4464.3,2165 4425,2165 v1@4405.9,2184.1
  Bottom Layer w12: v1(4405.9,2183.59) 4359.79,2229.7 4359.79,2258.72 4375.02,2273.96 4534.41,2273.96 4610.45,2350 P6.4@4800,2350
FAULT: P6.2 U4.14 U5.12 | length 1209.3
  Top Layer w12: U4.14@4314.6,2299.9 4314.6,2299.96 v1(4394.09,2299.96) 4454.05,2240 4514.9,2240 4534.9,2220 4534.9,2088.9 U5.12@4535.5,2088.3
  Bottom Layer w12: v1(4394.09,2299.96) 4332,2299.96 4310,2277.96 4310,2099 4334,2075 4675,2075 P6.2@4800,1950
GPIO0/I2C(SDA): P5.3 R192.1 U5.2 | length 1201.3
  Top Layer w12: R192.1@4550,2443.5 4612.4,2381.1 4612.4,2307.3 4612.4,2187.86 4690,2110.26 4690,1385 P5.3@4750,1325
GPIO1/I2C(SCL): P5.1 R191.1 U5.1 | length 1069.9
  Top Layer w12: R191.1@4650,2443.5 4650,2380 4638,2368 4638,2307.3 4638,2205.04 4710.5,2132.54 4710.5,1685 4750,1645.5 P5.1@4750,1425
NetC22_2: C22.2 R84.1 R89.2 TP-2.1 U1.20 | length 1021.2
  Top Layer w8: TP-2.1@1910,710 1942,710 1992,660 2025,660 2061,624 2248.48,624 2280.7,656.22 2280.7,806.2 ; TP-2.1@1955,711 TP-2.1@1959,711 ; C22.2@2235,760 2235,792.92 2248.28,806.2 2280.7,806.2 ; U1.20@2261.42,1054.61 2261.42,986.58 2319,929 2319,891.5 R89.2@2276,848.5 ; R89.2@2280.7,845 2280.7,806.2 ; R84.1@2316.29,760 2316.29,797.72 2307.81,806.2 2280.7,806.2
NetC23_2: C23.2 R85.1 R91.2 TP-4.1 U1.61 | length 866.2
  Top Layer w8: TP-4.1@2100,2020 2197,2020 2255,1962 2255,1774 ; R85.1@2210,1818.5 2210,1785.06 2221.06,1774 2255,1774 ; 2233.4,1773.94 2233.4,1754.6 2223.25,1744.46 2223.25,1604.21 2261.42,1566.05 U1.61@2261.42,1505.39 ; R91.2@2260,1721.5 2255,1726.5 2255,1774 ; C23.2@2290,1818.5 2290,1785 2279,1774 2255,1774
NetC31_1: C31.1 C33.2 R106.1 R108.1 U1.47 | length 715.6
  Top Layer w8: U1.47@2575.39,1407.95 2609.95,1407.95 2705,1503 ; C33.2@2705,1528.5 2705,1503 ; C31.1@2783.5,1480 2745,1480 ; R108.1@2783.5,1555 2754,1555 2745,1546 2745,1516 ; R106.1@3015,1643.5 3015,1640 2891,1516 2745,1516 ; 2705,1503 2728,1480 2745,1480 ; 2745,1480 2745,1516
NetC32_1: C32.1 C33.1 R99.1 R101.1 U1.48 | length 777.2
  Top Layer w8: U1.48@2575.39,1427.64 2606.04,1427.64 2663.85,1485.45 2663.85,1581.85 2677,1595 2705,1595 2705,1672.9 2737.1,1705 2746.06,1705 ; 2749.31,1630 R101.1@2780,1630 ; C32.1@2780,1705 2746.06,1705 ; R99.1@2940,1640 2891.56,1591.56 2752.05,1591.56 2744.89,1598.72 2744.89,1703.83 2746.06,1705
NetC39_1: C39.1 U1.16 | length 291.8
  Top Layer w8: 2066,1117 2081.36,1132.36 U1.16@2124.61,1132.36
  Top Layer w12: C39.1@2005,915.43 2005,1056 2066,1117
NetC58_2: C58.2 R127.1 R132.2 TP-8.1 U2.20 | length 901.7
  Top Layer w8: TP-8.1@2070,2765 2078,2757 2252,2757 2282.66,2787.66 2282.66,2935.17 ; R127.1@2240,2895 2240,2922.05 2253.12,2935.17 2282.66,2935.17 ; U2.20@2261.42,3221.65 2261.42,3158.06 2332.16,3087.32 2332.16,2954.33 2309.8,2931.98 ; R132.2@2280,2985 2282.66,2985 2282.66,2935.17 ; C58.2@2320,2895 2320,2921.78 2309.8,2931.98 ; 2282.66,2935.17 2306.61,2935.17 2309.8,2931.98
NetC59_2: C59.2 R128.1 R134.2 TP-10.1 U2.61 | length 914.4
  Top Layer w8: TP-10.1@2040,4260 2090,4210 2090,4196.07 2130.1,4155.97 2193,4155.97 2244,4104.97 2244,3950 2260,3950 ; C59.2@2210,3995 2210,3960 2220,3950 ; 2240,3950 2220,3950 ; R134.2@2260,3905 2260,3950 ; U2.61@2261.42,3678.35 2261.42,3723.63 2225,3760.05 2225,3945 2220,3950 ; R128.1@2285,3995 2285,3960 2275,3950 2260,3950
NetC70_1: C70.1 C72.2 R144.1 R146.1 U2.47 | length 849.8
  Top Layer w8: U2.47@2578.35,3577.95 2606.76,3577.95 2608.81,3580 2660,3580 2720,3640 ; C72.2@2720,3685 2720,3640 ; C70.1@2795,3640 2760,3640 ; R146.1@2795,3715 2765,3715 2760,3710 2760,3680 ; R144.1@3110,3800 3110,3705 3085,3680 2760,3680 ; 2720,3640 2760,3640 ; 2760,3640 2760,3680
NetC71_1: C71.1 C72.1 R140.1 R141.1 U2.48 | length 851.5
  Top Layer w8: U2.48@2578.35,3597.64 2612.64,3597.64 2635,3620 2635,3725 2700,3790 2720,3790 ; C72.1@2720,3755 2720,3790 ; C71.1@2795,3790 2755,3790 ; R141.1@2795,3865 2765,3865 2755,3855 2755,3790 ; R140.1@3035,3800 3035,3775 3010,3750 2765,3750 2755,3760 2755,3790 ; 2720,3790 2755,3790
NetC77_1: C77.1 U2.16 | length 290
  Top Layer w8: 2069,3292 2079.36,3302.36 U2.16@2124.61,3302.36
  Top Layer w16: C77.1@2000,3090.43 2000,3223 2069,3292
NetC96_2: C96.2 R165.1 R169.2 TP-14.1 U3.20 | length 1025.3
  Top Layer w8: TP-14.1@1975,4925 2040,4925 2055,4940 2055,4975 2085,5005 2220,5005 2245,5030 2245,5220 ; R165.1@2210,5165 2210,5205 2225,5220 2245,5220 ; R169.2@2260,5270 2260,5220 ; U3.20@2261.42,5471.65 2261.42,5393.58 2300,5355 2300,5240 2280,5220 ; C96.2@2290,5165 2290,5210 2280,5220 ; 2245,5220 2260,5220 ; 2260,5220 2280,5220
NetC97_2: C97.2 R166.1 R170.2 TP-16.1 U3.61 | length 834.5
  Top Layer w8: TP-16.1@2100,6355 2160,6355 2175,6370 2250,6370 2265,6355 2265,6175 ; C97.2@2220,6228.5 2220,6190 2235,6175 ; U3.61@2261.42,5928.35 2261.42,5975 2226.42,6010 2226.42,6166.42 2235,6175 ; R170.2@2265,6135 2265,6175 ; R166.1@2300,6228.5 2300,6185 2290,6175 2265,6175 ; 2235,6175 2265,6175
NetC104_1: C104.1 C106.2 R184.1 R185.1 U3.47 | length 896.3
  Top Layer w8: U3.47@2578.35,5827.95 2615,5827.95 2677.05,5890 2710,5890 ; C106.2@2710,5945 2710,5890 ; C104.1@2795,5890 2755,5890 ; R185.1@2795,5970 2765,5970 2755,5960 2755,5925 ; R184.1@3135,6065 3135,5985 3075,5925 2755,5925 ; 2710,5890 2755,5890 ; 2755,5890 2755,5925
NetC105_1: C105.1 C106.1 R179.1 R181.1 U3.48 | length 915.7
  Top Layer w8: U3.48@2578.35,5847.64 2612,5847.64 2635,5870.64 2635,6015 2670,6050 2710,6050 ; C106.1@2710,6015 2710,6050 ; R181.1@2795,6050 2745,6050 ; C105.1@2795,6130 2755,6130 2745,6120 2745,6050 ; R179.1@3045,6065 3045,6025 3030,6010 2770,6010 2745,6035 2745,6050 ; 2710,6050 2745,6050
NetC112_1: C112.1 U3.16 | length 303.9
  Top Layer w8: 2055,5525 2055,5529 2078.36,5552.36 U3.16@2124.61,5552.36
  Top Layer w15: C112.1@1980,5335.43 1980,5410 2025,5455 2025,5480 2055,5510 2055,5525
NetC120_1: C120.1 C123.1 C135.1 D4.1 D4.2 D4.5 D4.6 D4.8 R212.1 TP-20.1 U4.1 U4.7 U6.10 U6.16 U9.5 | length 1223.3
  Top Layer w12: 3570,1175 R212.1@3615,1175 ; v1(3715,1875) 3715.1,1875.1 U6.10@3785.4,1875.1 ; v1(3765,2345) 3796,2345 3810.43,2359.43 C135.1@3810.43,2400 v1(3860,2400) 3860.1,2399.9 U4.1@3935.6,2399.9 ; v1(3865,2100) 3865.1,2099.9 U4.7@3935.6,2099.9
  Top Layer w15: v1(3570,1245) 3570,1175 3570,1149 3613,1106 U9.5@3613,1092
  Top Layer w20: C123.1@3681.5,1575 v1(3722,1575) ; TP-20.1@3725,1380 3722,1383 v1(3722,1575) ; U6.16@3787.99,1575 v1(3722,1575)
  Bottom Layer w12: v1(3520,2100) v1(3765,2345)
NetC126_1: C126.1 JP19.1 U7.5 | length 238.7
  Top Layer w20: JP19.1@4177,1425 4231,1425 ; U7.5@4287.6,1354.13 4250.87,1354.13 4231,1374 4231,1425 ; C126.1@4289.57,1450 4264.57,1425 4231,1425
NetC127_1: C127.1 C128.1 C129.1 C133.1 C134.1 R210.2 R211.1 T1.2 TP-SW1.1 U7.1 U8.8 | length 2382.8
  Top Layer w24: R211.1@4100,1035 4100,1238.28 4136.72,1275 4226.39,1275 4246.39,1255 4288,1255 4288,1215.23 4332.67,1170.56 4416.51,1170.56 4432.5,1154.57 4432.5,1115 4500,1115 4500,1025 ; C133.1@4390,525 4390,450 4437.78,402.22 4519.8,402.22 4537.02,385 4600,385 4600,465 4564,465 4545,484 4545,585 4600,640 4675,640 ; U8.8@4444,1025 4500,1025 ; TP-SW1.1@4825,640 4675,640 ; 4500,1025 4675,850 4675,640
  Top Layer w30: T1.2@4221.6,501 4277,501 4328,450 C134.1@4390,450
NetC130_1: C130.1 L1.2 U9.1 | length 277.3
  Top Layer w20: L1.2@3525,865 3532,865 3574.5,907.5 ; C130.1@3526,993.5 3526,956 3574.5,907.5 ; U9.1@3612.6,995.87 3612.6,945.6 3574.5,907.5
NetC131_1: C131.1 C132.1 L1.1 T1.5 | length 895.5
  Top Layer w24: L1.1@3525,780 3525,725 3535,715 3650,715 ; C132.1@3650,765 3650,715 ; C131.1@3750,765 3750,715 ; T1.5@3896.4,501 3966,501 3995,530 3995,665 3945,715 3750,715 ; 3650,715 3750,715
NetC136_1: C136.1 R211.2 U8.4 | length 274.7
  Top Layer w10: R211.2@4100,968.5 C136.1@4100,856.5 4158.5,856.5 4177,875 U8.4@4255,875
NetD1_1: D1.1 R77.1 | length 116
  Top Layer w8: R77.1@2916.5,680 D1.1@3032.52,680
NetD1_2: D1.2 Q5.1 Q5.2 Q5.5 Q5.6 Q5.8
NetD2_1: D2.1 R123.1 | length 106
  Top Layer w8: R123.1@2916.5,2840 D2.1@3022.52,2840
NetD2_2: D2.2 Q12.1 Q12.2 Q12.5 Q12.6 Q12.8
NetD3_1: D3.1 R161.1 | length 106
  Top Layer w8: R161.1@2916.5,5120 D3.1@3022.52,5120
NetD3_2: D3.2 Q20.1 Q20.2 Q20.5 Q20.6 Q20.8 | length 320.4
  Top Layer w8: Q20.8@3077.8,5240 3175,5240 3190,5225 3190,5130 3180,5120 3087.3,5120 D3.2@3087.2,5120.1
NetD4_3: D4.3 R196.2 | length 88.1
  Top Layer w8: R196.2@3585,2000 3585,2036.16 3600.59,2051.75 D4.3@3600.59,2081.69
NetD4_4: D4.4 D4.7 R193.1 R202.2
NetD5_1: D5.1 T1.6 | length 172.1
  Top Layer w10: D5.1@3747.5,345 3803.5,401 T1.6@3896.4,401
NetD6_1: D6.1 T1.4 | length 170
  Top Layer w10: D6.1@3747.5,550 3798.5,601 T1.4@3896.4,601
NetJ1_2: J1.2 R68.1 TP-C2.1 | length 1836.2
  Top Layer w12: TP-C2.1@1825,2180 1930,2075 R68.1@1930,1825
  Top Layer w25: J1.2@555,1935 880,2260 1695,2260 1775,2180 TP-C2.1@1825,2180
NetJ2_1: J2.1 R84.2 RT1.1 | length 4917.6
  Top Layer w8: R84.2@2315,693.5 2317,691.5 v1(2317,651) ; J2.1@4447,4359 4487,4319 4533,4319 4550,4336 RT1.1@4550,4388.5
  Bottom Layer w8: v1@2314.4,653.42 2483.42,653.42 2806,976 2806,1783.19 4450,3427.19 J2.1@4450,4365
NetJ3_1: J3.1 R85.2 RT2.1 | length 3973.7
  Top Layer w8: RT2.1@4200,4388.5 4200,4340 4223,4317 4256,4317 J3.1@4298,4359
  Top Layer w10: R85.2@2210,1881.5 v1(2210.03,1926.43)
  Top Layer w24: R85.2@2209,1878 R85.2@2210.03,1878
  Bottom Layer w8: v1@2209.8,1923.12 2233.8,1947.12 2328.52,1947.12 2379.64,1896 2872.79,1896 4300,3323.21 J3.1@4300,4365
NetJ4_2: J4.2 R115.1 TP-C4.1 | length 2044.2
  Top Layer w24: J4.2@561,4080 561,4081 704.92,4224.92 704.92,4381.59 849.79,4526.46 1693.54,4526.46 1785,4435 1785,4230 1910,4105 1910,4010 R115.1@1930,3990
NetJ5_1: J5.1 R127.2 RT3.1 | length 4083.1
  Top Layer w8: v1(2240.03,2786.19) R127.2@2240.03,2829.53 ; J5.1@4425,5271 4468,5228 4536,5228 4550,5242 RT3.1@4550,5298.5
  Bottom Layer w8: v1@2239.33,2786.74 2239.33,2755.49 2250.96,2743.86 2356.24,2743.86 2397.59,2785.2 2397.59,3082.03 2454.49,3138.94 2760,3138.94 2975.75,3355 2975.75,3871.15 2989.72,3885.12 3192.48,3885.12 4425,5117.64 J5.1@4425,5271
NetJ6_1: J6.1 R128.2 RT4.1 | length 3069.4
  Top Layer w8: RT4.1@4175,5298.5 4175,5252 4198,5229 4257,5229 J6.1@4300,5272
  Top Layer w24: R128.2@2285,4064 v1(2285.03,4099.43)
  Bottom Layer w8: v1@2285.19,4102.12 2285.19,4018.66 2372.76,3931.09 3193.2,3931.09 4300,5037.89 J6.1@4300,5272 J6.1@4300,5280
NetJ7_2: J7.2 R152.1 TP-C6.1 | length 2785.8
  Top Layer w10: TP-C6.1@1785,6755 TP-C6.1@1790,6755 1815,6755 1845,6725 v3(1845,6670) ; v1(1890,6285) 1890,6267 R152.1@1927,6230
  Top Layer w24: J7.2@560,5855 695,5990 695,6801 774,6880 1640,6880 1762,6758 1782,6758 TP-C6.1@1785,6755 ; R152.1@1927,6230 R152.1@1927,6238
  Bottom Layer w10: v3(1845,6670) 1890,6625 v1(1890,6285)
NetJ8_1: J8.1 R165.2 RT5.1 | length 3398.9
  Top Layer w8: R165.2@2209,5098.5 2210,5097.5 v1(2210,5055) ; J8.1@4426,6208 4472,6162 4511,6162 4525,6176 RT5.1@4525,6218.5
  Bottom Layer w8: v1@2210,5050 2245,5015 2300,5015 2315,5030 2315,5345 2360,5390 2725,5390 2930,5595 2930,5675 2975,5720 2975,6005 2990,6020 4350,6020 4425,6095 4425,6207 J8.1@4426,6208
NetJ9_1: J9.1 R166.2 RT6.1 | length 2469.2
  Top Layer w8: R166.2@2300,6291.5 2301,6292.5 v1(2301,6340) ; RT6.1@4200,6218.5 4200,6185 4222,6163 4251,6163 J9.1@4297,6209
  Bottom Layer w8: v1(2301,6340) 2390,6251 2899,6251 2970,6180 2970,6100 2995,6075 4250,6075 4300,6125 4300,6206 J9.1@4297,6209
NetJP1_2: JP1.2 R13.1 | length 144.8
  Top Layer w24: JP1.2@556,5598 698,5598 R13.1@700,5600
NetJP2_2: JP2.2 R14.1 | length 144.8
  Top Layer w24: JP2.2@556,5448 698,5448 R14.1@700,5450
NetJP3_2: JP3.2 R15.1 | length 144.8
  Top Layer w24: JP3.2@556,5298 698,5298 R15.1@700,5300
NetJP4_2: JP4.2 R16.1 | length 144.8
  Top Layer w24: JP4.2@556,5148 698,5148 R16.1@700,5150
NetJP5_2: JP5.2 R17.1 | length 144.8
  Top Layer w24: JP5.2@556,4998 698,4998 R17.1@700,5000
NetJP6_2: JP6.2 R18.1 | length 144.8
  Top Layer w24: JP6.2@556,4848 558,4850 R18.1@700,4850
NetJP7_2: JP7.2 R30.1 | length 144.4
  Top Layer w24: JP7.2@556,3854 635,3854 636,3855 R30.1@700,3855
NetJP8_2: JP8.2 R31.1 | length 144.4
  Top Layer w24: JP8.2@556,3704 635,3704 636,3705 R31.1@700,3705
NetJP9_2: JP9.2 R32.1 | length 144.4
  Top Layer w24: JP9.2@556,3554 635,3554 636,3555 R32.1@700,3555
NetJP10_2: JP10.2 R33.1 | length 144.4
  Top Layer w24: JP10.2@556,3404 635,3404 636,3405 R33.1@700,3405
NetJP11_2: JP11.2 R34.1 | length 144.4
  Top Layer w24: JP11.2@556,3254 635,3254 636,3255 R34.1@700,3255
NetJP12_2: JP12.2 R35.1 | length 144.4
  Top Layer w24: JP12.2@556,3104 635,3104 636,3105 R35.1@700,3105
NetJP13_2: JP13.2 R47.1 | length 144
  Top Layer w24: JP13.2@556,1740 R47.1@700,1740
NetJP14_2: JP14.2 R48.1 | length 144
  Top Layer w24: JP14.2@556,1590 R48.1@700,1590
NetJP15_2: JP15.2 R49.1 | length 144
  Top Layer w24: JP15.2@556,1440 R49.1@700,1440
NetJP16_2: JP16.2 R50.1 | length 144
  Top Layer w24: JP16.2@556,1290 R50.1@700,1290
NetJP17_2: JP17.2 R51.1 | length 144
  Top Layer w24: JP17.2@556,1140 R51.1@700,1140
NetJP18_2: JP18.2 R52.1 | length 144
  Top Layer w24: JP18.2@556,990 R52.1@700,990
NetP4_4: P4.4 R1.2 | length 558.1
  Top Layer w8: R1.2@2020,6597.09 2020,6653 2261,6894 2346,6894 P4.4@2400,6840
NetP4_7: P4.7 R10.2 | length 281.6
  Top Layer w8: v1(2737,6646) 2737,6645 2750,6632 R10.2@2750,6561.09
  Bottom Layer w8: P4.7@2600,6740 2658,6682 2727.24,6682 2737,6672.24 v1(2737,6646)
NetP4_8: P4.8 R12.2 | length 560.8
  Top Layer w8: R12.2@2958.87,6560.9 R12.2@2959.06,6561.08 ; R12.2@2972.87,6559.9 2972.97,6560 v1(2972.97,6607.69)
  Bottom Layer w8: P4.8@2600,6840 2650,6790 2865,6790 2972.97,6682.03 v1(2972.97,6607.69)
NetP4_10: P4.10 R11.2 | length 346.6
  Top Layer w10: P4.10@2700,6840 2858,6682 2858,6561.72 R11.2@2860,6559.72
NetP8_1: P8.1 R55.1 | length 463.8
  Top Layer w8: R55.1@2053,417.4 2055,415.4 v1(2055,362)
  Bottom Layer w8: v1(2055,362) 2055,233 2148,140 P8.1@2295,140
NetP8_2: P8.2 R54.1 | length 467.7
  Top Layer w8: R54.1@1943,418.4 1943,347 2050,240 P8.2@2295,240
NetP8_3: P8.3 R56.1 | length 423.3
  Top Layer w8: R56.1@2163,417.4 2163,358 2218,303 2303,303 2348,258 2348,187 P8.3@2395,140
NetP8_9: P8.9 R65.1 | length 410.6
  Top Layer w8: P8.9@2695,140 2788,140 2879,231 R65.1@2879,419.91
NetQ1_1: Q1.1 Q1.2 Q1.5 Q1.6 Q1.8 R66.1
NetQ1_3: Q1.3 R69.2 R71.2 Z3.1
NetQ2_1: Q2.1 Q2.2 Q2.5 Q2.6 Q2.8 R70.1 U1.43 | length 773.8
  Top Layer w8: U1.43@2578.35,1329.21 2544.21,1329.21 2532,1317 2532,1127 2555.79,1103.21 2884.79,1103.21 2985,1003 R70.1@2985,975
NetQ2_3: Q2.3 R73.2 R75.2 | length 366.4
  Top Layer w8: Q2.3@3125.59,931.69 3146.69,931.69 3155,940 R75.2@3193.5,940 3193.5,912.5 3206,900 3315,900 3340,925 R73.2@3340,1030.5
NetQ3_1: Q3.1 Q3.2 Q3.5 Q3.6 Q3.8 R74.1
NetQ3_3: Q3.3 R76.2 R78.2 Z5.1
NetQ4_1: Q4.1 Q4.2 Q4.5 Q4.6 Q4.8 R81.1
NetQ4_3: Q4.3 R87.2 R90.2 Z7.1
NetQ5_3: Q5.3 R88.1 | length 198.9
  Top Layer w8: R88.1@2926,831.5 2926,869 2949,892 3027,892 3044.41,874.59 Q5.3@3044.41,848.31
NetQ6_1: Q6.1 Q6.2 Q6.5 Q6.6 Q6.8 R93.1
NetQ6_3: Q6.3 R95.2 R97.2 Z9.1
NetQ7_1: Q7.1 Q7.2 Q7.5 Q7.6 Q7.8 R100.1
NetQ7_3: Q7.3 R102.2 R107.2 Z11.1
NetQ8_1: Q8.1 Q8.2 Q8.5 Q8.6 Q8.8 R110.1
NetQ8_3: Q8.3 R111.2 R112.2 Z13.1
NetQ9_1: Q9.1 Q9.2 Q9.5 Q9.6 Q9.8 R113.1
NetQ9_3: Q9.3 R116.2 R117.2 Z16.1
NetQ10_1: Q10.1 Q10.2 Q10.5 Q10.6 Q10.8 R119.1
NetQ10_3: Q10.3 R120.2 R121.2 Z18.1
NetQ11_1: Q11.1 Q11.2 Q11.5 Q11.6 Q11.8 R124.1
NetQ11_3: Q11.3 R125.2 R129.2 Z20.1
NetQ12_3: Q12.3 R130.2 | length 206.2
  Top Layer w8: R130.2@2915,2995 2915,3037.37 2925.38,3047.75 3023.59,3047.75 3039.41,3031.92 3039.41,3003.31
NetQ13_1: Q13.1 Q13.2 Q13.5 Q13.6 Q13.8 R133.1
NetQ13_3: Q13.3 R136.2 R137.2 Z22.1
NetQ14_1: Q14.1 Q14.2 Q14.5 Q14.6 Q14.8 R139.1
NetQ14_3: Q14.3 R142.2 R143.2 Z24.1
NetQ15_1: Q15.1 Q15.2 Q15.5 Q15.6 Q15.8 R147.1
NetQ15_3: Q15.3 R148.2 R149.2 Z26.1
NetQ16_1: Q16.1 Q16.2 Q16.5 Q16.6 Q16.8 R150.1
NetQ16_3: Q16.3 R153.2 R154.2 Z29.1
NetQ17_1: Q17.1 Q17.2 Q17.5 Q17.6 Q17.8 R156.1
NetQ17_3: Q17.3 R157.2 R158.2 Z31.1
NetQ18_1: Q18.1 Q18.2 Q18.5 Q18.6 Q18.8 R160.1
NetQ18_3: Q18.3 R162.2 R163.2 Z33.1
NetQ19_1: Q19.1 Q19.2 Q19.5 Q19.6 Q19.8 R167.1
NetQ19_3: Q19.3 R173.2 R174.2 Z35.1
NetQ20_3: Q20.3 R171.2 | length 220.6
  Top Layer w8: R171.2@2915,5275 2915,5324.41 2925,5334.41 3025,5334.41 3039.41,5320 Q20.3@3039.41,5283.31
NetQ21_1: Q21.1 Q21.2 Q21.5 Q21.6 Q21.8 R176.1
NetQ21_3: Q21.3 R178.2 R180.2 Z37.1
NetQ22_1: Q22.1 Q22.2 Q22.5 Q22.6 Q22.8 R183.1
NetQ22_3: Q22.3 R186.2 R187.2 Z39.1
NetQ23_1: Q23.1 Q23.2 Q23.5 Q23.6 Q23.8 T1.1
NetQ23_3: Q23.3 U8.7 | length 922.3
  Top Layer w12: v1(4369.02,975.07) 4444,975.07 U8.7@4444,975 ; Q23.3@4400.59,281.69 4400.59,280.93 v1(4448.21,280.93)
  Bottom Layer w12: v1(4369.02,975.07) 4535,809.09 4535,367.71 v1(4448.21,280.93)
NetQ23_4: Q23.4 Q23.7 Q24.4 Q24.7 R214.2 R215.2 | length 631.6
  Top Layer w12: v1(4435,695) 4435,723.29 4426.44,731.85 4391.6,731.85 4385,738.45 4385,775 4420,775 4460,735 R215.2@4500,735
  Bottom Layer w12: v1(4435,365) 4376,424 4376,636 v1(4435,695)
NetQ24_1: Q24.1 Q24.2 Q24.5 Q24.6 Q24.8 T1.3
NetQ24_3: Q24.3 U8.6 | length 498.3
  Top Layer w12: v1(4380.63,925.58) 4444,925.58 U8.6@4444,925 ; Q24.3@4400.59,606.69 4400.59,608.93 v1(4428.21,608.93)
  Bottom Layer w12: v1(4380.63,925.58) 4510.48,795.73 4510.48,691.19 v1(4428.21,608.93)
NetR86_1: R86.1 R88.2 U1.45 | length 909.8
  Top Layer w8: U1.45@2575.39,1368.58 2528.58,1368.58 2498,1338 2498,1109 2772,835 2831.5,835 R86.1@2835,831.5 2862.5,831.5 2879,815 2879,778 2888.5,768.5 R88.2@2926,768.5
NetR89_1: R89.1 TP-3.1 U1.19 | length 481.9
  Top Layer w8: TP-3.1@2077,710 2085,710 2172,797 2206,797 2242,833 2242,905 2248.5,911.5 R89.1@2276,911.5 2276,941 2241.73,975.27 U1.19@2241.73,1054.61
NetR91_1: R91.1 TP-1.1 U1.60 | length 695.5
  Top Layer w8: TP-1.1@2105,1885 2105,1925 2125,1945 v1(2155,1945) ; R91.1@2260,1658.5 2269,1649.5 v1(2269,1607) 2269,1581 2281.1,1568.9 U1.60@2281.1,1505.39
  Bottom Layer w8: v1(2155,1945) 2155,1910 2186,1879 2239,1879 2292,1826 2292,1630 v1(2269,1607)
NetR94_1: R94.1 R96.2 U1.44 | length 688.3
  Top Layer w8: U1.44@2575.39,1348.9 2535.9,1348.9 2514,1327 2514,1119 2548.29,1084.71 2790.29,1084.71 2801.5,1073.5 R96.2@2801.5,1050 R94.1@2801.5,970
NetR99_2: R99.2 TP-5.1 | length 496.9
  Top Layer w8: TP-5.1@2900,2140 2900,2135 2847,2082 2847,1803 2929,1721 2940,1721 R99.2@2940,1710
NetR106_2: R106.2 TP-6.1 | length 380.7
  Top Layer w8: TP-6.1@2900,2005 2965,2005 3015,1955 R106.2@3015,1710
NetR126_1: R126.1 R130.1 U2.45 | length 981.3
  Top Layer w8: U2.45@2578.35,3538.58 2539.58,3538.58 2527,3526 2527,3301 2653,3175 2690,3175 2835,3030 ; R126.1@2835,2995 2835,3030 ; R130.1@2915,2925 2915,2895 2910,2890 2885,2890 2875,2900 2875,3020 2860,3035 2840,3035 2835,3030
NetR132_1: R132.1 TP-9.1 U2.19 | length 545.2
  Top Layer w8: TP-9.1@2070,2905 2162.27,2905 2241.14,2983.87 2241.14,3111.62 2263.19,3133.67 ; U2.19@2241.73,3221.65 2241.73,3155.12 2263.19,3133.67 ; R132.1@2280,3055 2280,3116.85 2263.19,3133.67
NetR134_1: R134.1 TP-7.1 U2.60 | length 640.2
  Top Layer w8: R134.1@2260,3835 2260.79,3835 v1(2260.79,3791.93) 2260.79,3749.14 2281.1,3728.82 U2.60@2281.1,3678.35
  Top Layer w24: TP-7.1@2040,4115 v3(2135,4115)
  Bottom Layer w8: v3(2135,4115) 2130,4110 2130,4025 2220,3935 2220,3832.72 v1(2260.79,3791.93)
NetR135_1: R135.1 U2.44 | length 242.3
  Top Layer w8: U2.44@2575.39,3518.9 2608.1,3518.9 2625,3502 2625,3438 2659,3404 2684.5,3404 R135.1@2718.5,3370
NetR140_2: R140.2 TP-11.1 | length 140
  Top Layer w8: R140.2@3035,3870 TP-11.1@3035,4010
NetR144_2: R144.2 TP-12.1 | length 185.7
  Top Layer w12: R144.2@3110,3870 3140,3870 3178,3908 TP-12.1@3178,4010
NetR168_1: R168.1 R171.1 U3.45 | length 1014.3
  Top Layer w8: U3.45@2575.39,5788.58 2545,5788.58 2530,5773.58 2530,5535 2730,5335 2820,5335 2835,5320 ; R168.1@2835,5271.5 2835,5320 ; R171.1@2915,5208.5 2915,5175 2905,5165 2885,5165 2875,5175 2875,5324 2864,5335 2850,5335 2835,5320
NetR169_1: R169.1 TP-15.1 U3.19 | length 605.7
  Top Layer w8: TP-15.1@1975,5075 2045,5075 2220,5250 2220,5368.27 2241.73,5390 ; U3.19@2241.73,5471.65 2241.73,5390 ; R169.1@2260,5340 2260,5371.73 2241.73,5390
NetR170_1: R170.1 TP-13.1 U3.60 | length 846.1
  Top Layer w8: R170.1@2265,6065 v1(2265,6030) 2281.1,6013.9 U3.60@2281.1,5928.35
  Top Layer w12: v3(1920,6425) 1920,6365.75 TP-13.1@1930.75,6355
  Bottom Layer w8: v3(1920,6425) 1920,6220.59 2110.59,6030 v1(2265,6030)
NetR172_1: R172.1 U3.44 | length 257.5
  Top Layer w8: U3.44@2575.39,5768.9 2611.1,5768.9 2635,5745 2635,5655 2670,5620 R172.1@2718.5,5620
NetR179_2: R179.2 TP-17.1 | length 145
  Top Layer w8: R179.2@3045,6135 TP-17.1@3045,6280
NetR184_2: R184.2 TP-18.1 | length 177.4
  Top Layer w8: R184.2@3135,6135 3135,6250 3165,6280 TP-18.1@3185,6280
NetR188_2: R188.2 U4.3 | length 175.6
  Top Layer w12: R188.2@3760,2300 3760.1,2299.9 U4.3@3935.6,2299.9
NetR189_2: R189.2 U4.4 | length 185.9
  Top Layer w12: R189.2@3760,2225 3815.1,2225 3840,2249.9 U4.4@3935.6,2249.9
NetR190_1: R190.1 U5.6 | length 182
  Top Layer w10: R190.1@4450,2442.5 4487.5,2442.5 4510,2420 U5.6@4510,2307.3
NetR193_2: R193.2 U4.5 | length 196.3
  Top Layer w12: R193.2@3760,2150 3790.1,2150 3840,2199.9 U4.5@3935.6,2199.9
NetR194_2: R194.2 U4.6 | length 227.1
  Top Layer w12: R194.2@3760,2075 3805.1,2075 3820.1,2090 3820.1,2125 3845,2149.9 U4.6@3935.6,2149.9
NetR195_1: R195.1 U5.15 | length 174
  Top Layer w10: R195.1@4550,1956.5 4550,2006 4575,2031 4603,2031 4612.3,2040.3 U5.15@4612.3,2088.3
NetR197_1: R197.1 U6.14 | length 156.5
  Top Layer w20: R197.1@3631.5,1675 U6.14@3787.99,1675
NetR201_1: R201.1 U6.13 | length 166.9
  Top Layer w20: R201.1@3631.5,1750 3636,1750 3661,1725 U6.13@3787.99,1725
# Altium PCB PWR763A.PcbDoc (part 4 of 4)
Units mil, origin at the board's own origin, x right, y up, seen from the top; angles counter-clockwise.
Board outline 5000 x 7000 mil, 4 copper layers (Top Layer, Signal Layer 1, Signal Layer 2, Bottom Layer), stack 61.2 mil thick; 559 components, 281 nets, 1477 pads, 685 vias.

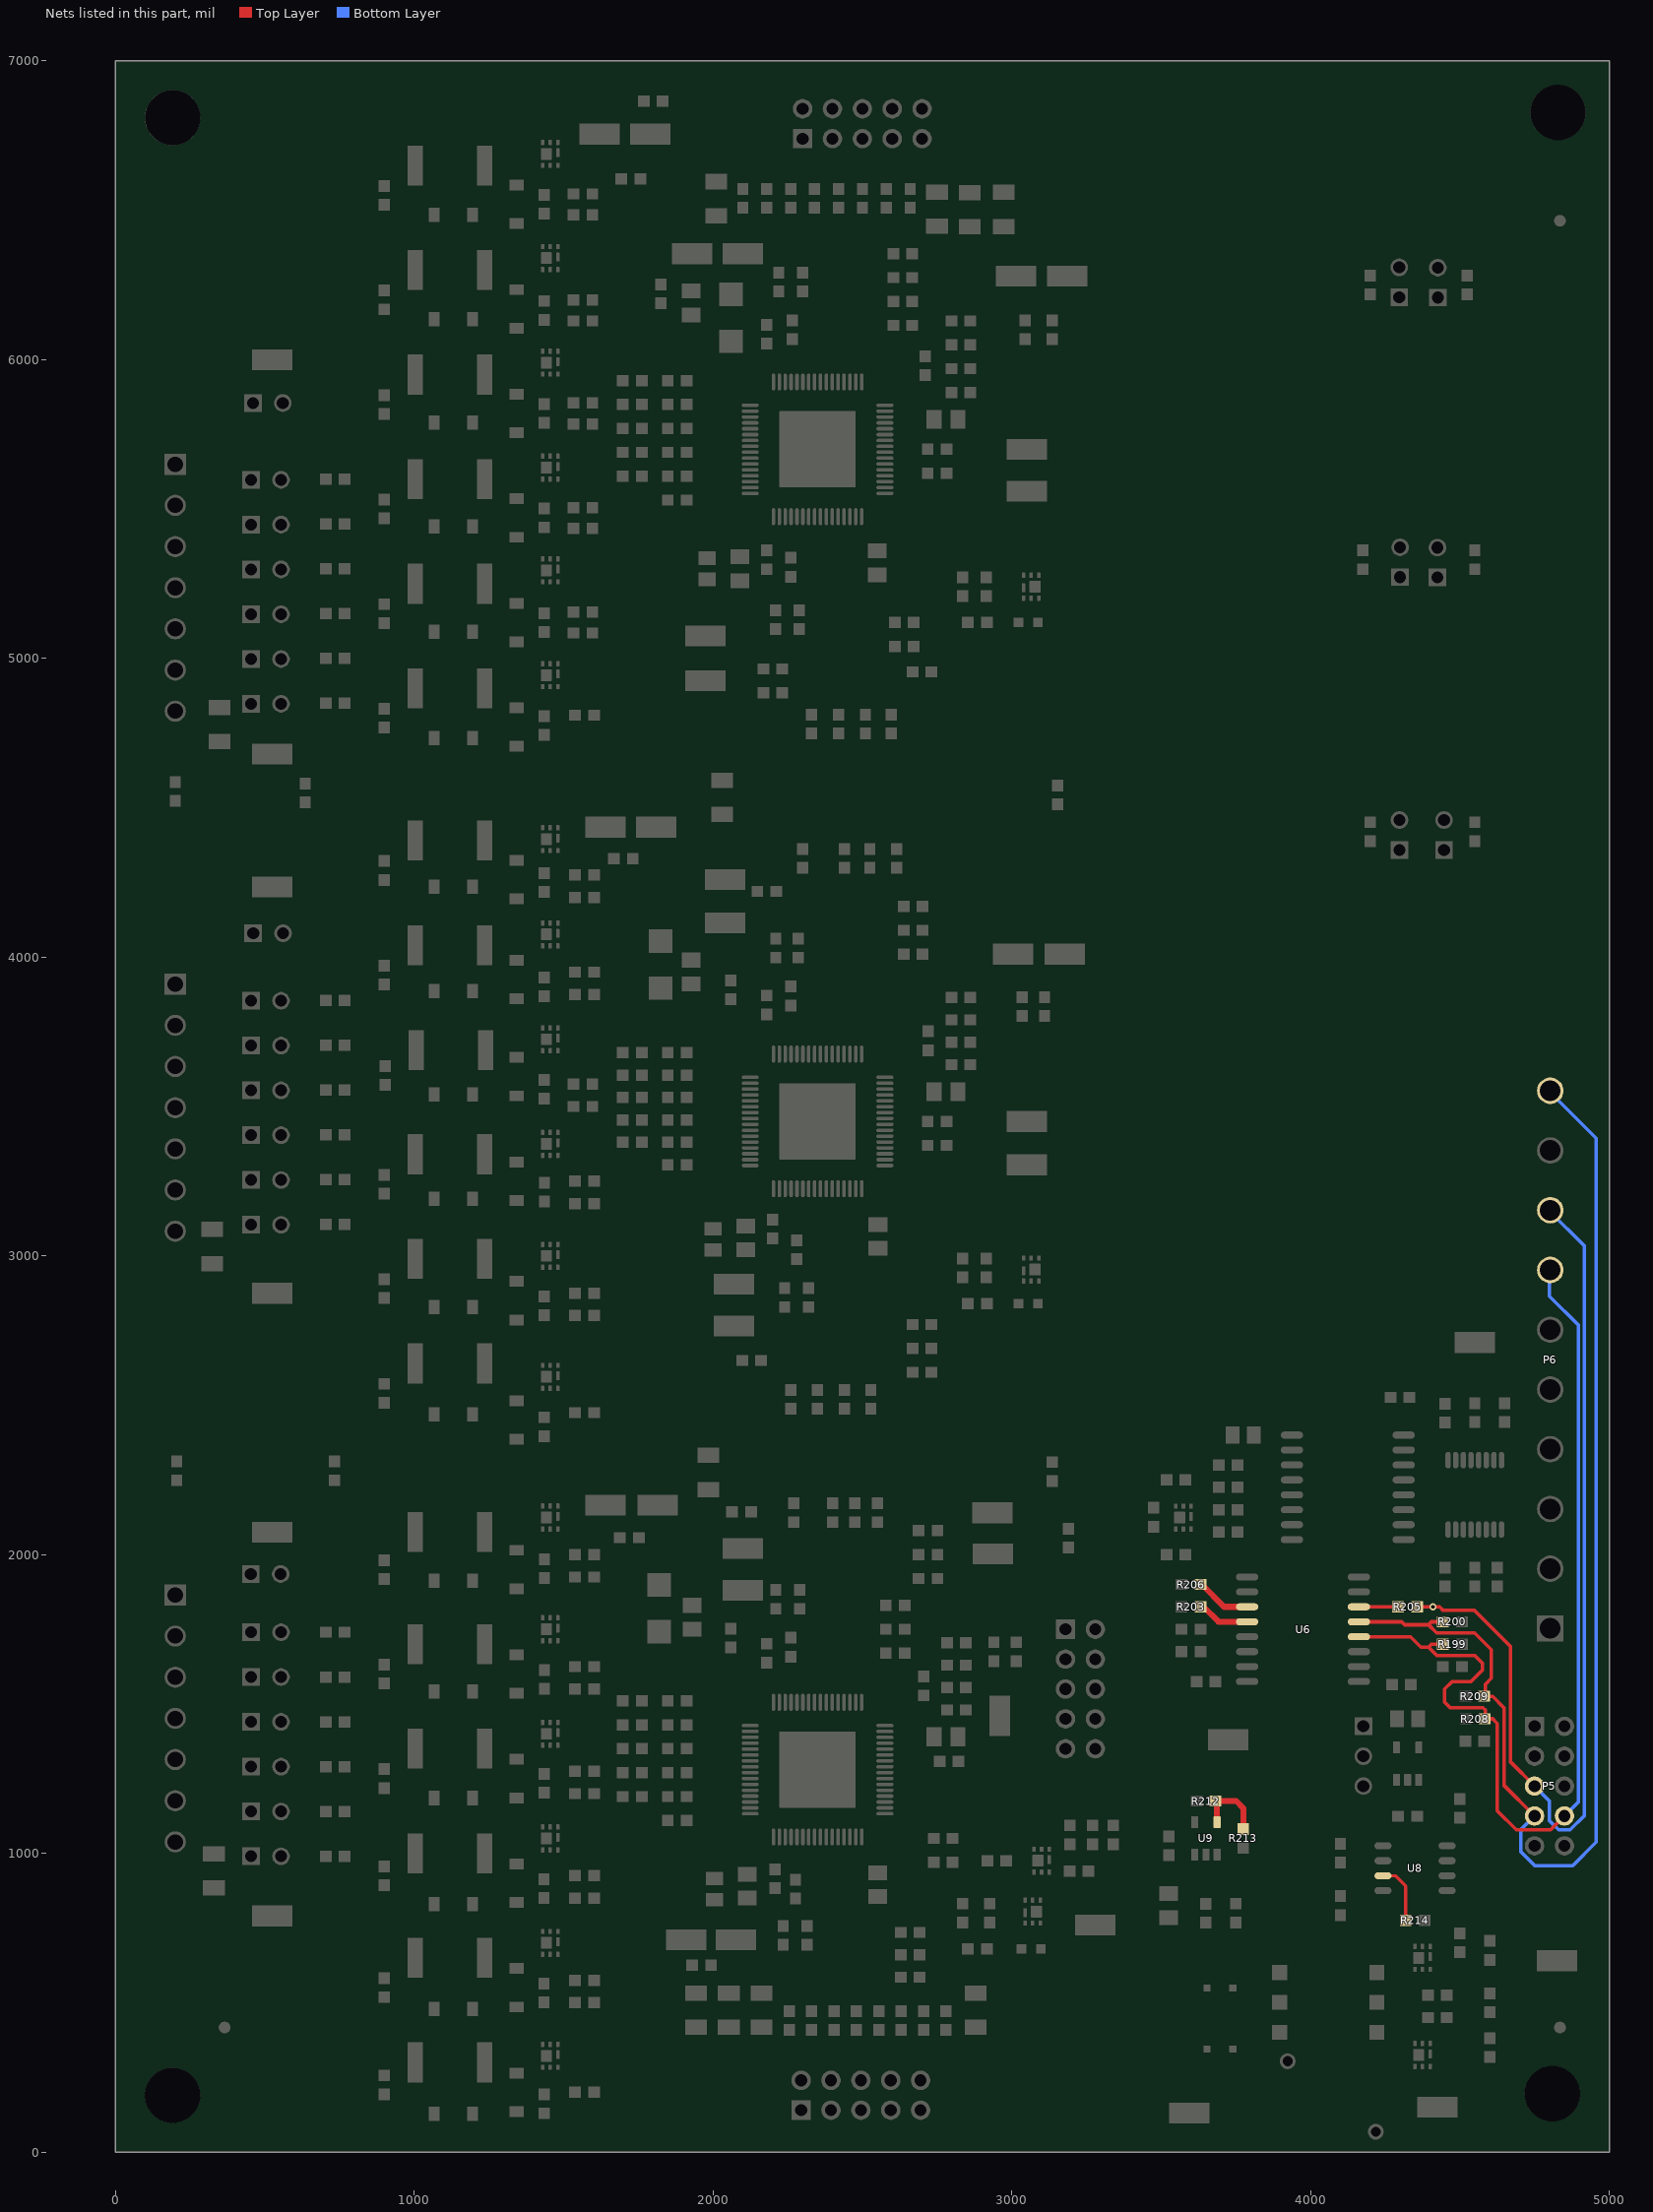
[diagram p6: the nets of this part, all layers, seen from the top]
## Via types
v1: diameter 24, hole 12, Top Layer to Bottom Layer, tented both sides, 607 vias
v2: diameter 19.68, hole 7.87, Top Layer to Bottom Layer, 75 vias
v3: diameter 22, hole 10, Top Layer to Bottom Layer, tented both sides, 3 vias

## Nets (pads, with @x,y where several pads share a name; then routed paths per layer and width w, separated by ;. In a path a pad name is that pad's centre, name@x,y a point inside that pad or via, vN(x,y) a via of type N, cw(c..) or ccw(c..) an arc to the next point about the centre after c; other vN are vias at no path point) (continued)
NetR203_1: R203.1 U6.12 | length 177.2
  Top Layer w20: R203.1@3631.5,1825 3642,1825 3692,1775 U6.12@3787.99,1775
NetR205_2: R205.2 U6.6 | length 131.5
  Top Layer w12: U6.6@4162.01,1825 R205.2@4293.5,1825
NetR206_1: R206.1 U6.11 | length 187.6
  Top Layer w20: R206.1@3631.5,1900 3636,1900 3711,1825 U6.11@3787.99,1825
NetR212_2: R212.2 R213.2 U9.4 | length 244
  Top Layer w20: R212.2@3681.5,1175 3751,1175 3775,1151 R213.2@3775,1081.5 ; R212.2@3687,1175 3687,1104.54 U9.4@3687.4,1104.13
NetR214_1: R214.1 U8.3 | length 193.3
  Top Layer w10: U8.3@4255,925 4284,925 4318.5,890.5 R214.1@4318.5,775
SCLK: P5.7 P6.10 R200.1 R209.2 U6.5 | length 4197.6
  Top Layer w12: U6.5@4164.4,1775.1 4164.5,1775 4305,1775 4315,1765 4395,1765 ; R200.1@4440,1775 4405,1775 4395,1765 ; P5.7@4750,1125 4647.48,1227.52 4647.48,1487.52 4610,1525 4585,1525 4585,1565.86 4605,1585.86 4605,1681.77 4549.27,1737.5 4422.5,1737.5 4395,1765
  Bottom Layer w12: P5.7@4750,1125 4703.5,1078.5 4703.5,1005.74 4750.74,958.5 4877.55,958.5 4956.5,1037.45 4956.5,3393.5 P6.10@4800,3550
SIMO: P5.8 P6.7 R199.1 R208.2 U6.4 | length 3387.4
  Top Layer w12: U6.4@4164.4,1725.1 4164.5,1725 4335,1725 4370,1690 4395,1690 ; R199.1@4440,1700 4405,1700 4395,1690 ; P5.8@4850,1125 4803.5,1078.5 4688.89,1078.5 4625,1142.39 4625,1435 4610,1450 4585,1450 4585,1480 4577.5,1487.5 4467.5,1487.5 4449,1506 4449,1550 4474,1575 4536.77,1575 4576,1614.23 4576,1635.77 4549.27,1662.5 4422.5,1662.5 4395,1690
  Bottom Layer w12: P6.7@4800,2950 4800,2865.25 4896.5,2768.75 4896.5,1171.5 P5.8@4850,1125
SOMI: P5.5 P6.8 R205.1 | length 3222.9
  Top Layer w12: R205.1@4360,1825 v1(4410,1825) 4432.62,1825 4444.62,1813 4548.77,1813 4670,1691.77 4670,1305 P5.5@4750,1225
  Bottom Layer w12: P5.5@4750,1225 4800,1175 4800,1109.24 4830.74,1078.5 4869.26,1078.5 4916.5,1125.74 4916.5,3033.5 P6.8@4800,3150
pads on no net: FID1.1 FID2.1 FID3.1 H1. H2. H3. H4. LBL1.0 P7.3 P7.4 P7.6 SH-J1.0 SH-J2.0 SH-J3.0 SH-J4.0 SH-J5.0 SH-J6.0 SH-J7.0 SH-J8.0 SH-JP1.0 SH-JP2.0 SH-JP3.0 SH-JP4.0 SH-JP5.0 SH-JP6.0 SH-JP7.0 SH-JP8.0 SH-JP9.0 SH-JP10.0 SH-JP11.0 SH-JP12.0 SH-JP13.0 SH-JP14.0 SH-JP15.0 SH-JP16.0 SH-JP17.0 SH-JP18.0 SH-JP19.0 U1.30 U1.31 U1.51 U1.62 U2.30 U2.31 U2.36 U2.37 U2.38 U2.39 U2.40 U2.41 U2.42 U2.43 U2.51 U2.62 U3.30 U3.31 U3.36 U3.37 U3.38 U3.39 U3.40 U3.41 U3.42 U3.43 U3.51 U3.62 U7.4 U8.1
copper on no net: | length 43.5
  Top Layer w20: v1(1805,5450) 1848.5,5450

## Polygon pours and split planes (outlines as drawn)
1-VC0 on Bottom Layer "Bottom-1-VSS" (solid, remove dead copper, pour order 24): 50,2250 50,50 4015,50 4015,2435 3545,2435 3465,2355 3465,2350 3365,2250 2625,2250 2625,1450 2225,1450 2225,2250
3-VC0 on Bottom Layer "Bottom-3-VSS" (solid, remove dead copper, pour order 22): 50,6950 50,4575 2275,4575 2275,3650 2625,3650 2625,4575 3390,4575 3390,6950
2-VC0 on Bottom Layer "Bottom-2-VSS" (solid, remove dead copper, pour order 21): 50,4500 50,2300 2250,2300 2250,1475 2629,1475 2629,2300 3250,2300 3400,2450 3400,4500 2650,4500 2650,3625 2250,3625 2250,4500
3-VC0 on Top Layer "Top-3-VSS" (solid, remove dead copper, pour order 18): 50,6950 50,4575 2275,4575 2275,3650 2625,3650 2625,4575 3390,4575 3390,6950
1-VC0 on Top Layer "Top-1-VSS" (solid, remove dead copper, pour order 19): 50,2250 50,50 4015,50 4015,2435 3545,2435 3465,2355 3465,2350 3365,2250 2625,2250 2625,1450 2225,1450 2225,2250
2-VC0 on Top Layer "Top-2-VSS" (solid, remove dead copper, pour order 16): 50,4500 50,2300 2250,2300 2250,1475 2600,1475 2600,2300 3400,2300 3400,4500 2650,4500 2650,3625 2250,3625 2250,4500
AGND on Signal Layer 1 "Signal Layer 2-No Net" (solid, pour order 17): 50,6950 3390,6950 3390,4580 3385,4575 50,4575
3.3_SW on Signal Layer 1 "Signal Layer 2-No Net 4" (solid, remove dead copper, pour order 26): 4075,2990 4675,2990 4675,3725 4965,3725 4965,50 4065,50 4065,2990
NetC120_1 on Signal Layer 1 "Signal Layer 2-No Net 3" (solid, remove dead copper, pour order 25): 3460,2350 3545,2435 4010,2435 4010,50 3460,50 3460,2325
1-VC0 on Signal Layer 1 "Signal Layer 2-No Net 2" (solid, remove dead copper, pour order 23): 50,2250 3400,2250 3400,50 50,50
2-VC0 on Signal Layer 1 "Signal Layer 2-No Net 1" (solid, remove dead copper, pour order 20): 50,4500 3400,4500 3400,2450 3250,2300 50,2300
AGND on Signal Layer 2 "Signal Layer 1-No Net 3" (solid, remove dead copper, pour order 30): 4065,2990 4675,2990 4675,3735 4965,3735 4965,35 4065,35 4065,2990 4675,2990 4675,3735 4675,2990
1-VC0 on Signal Layer 2 "Signal Layer 1-No Net 2" (solid, remove dead copper, pour order 29): 50,2250 2200,2250 2225,2250 2225,1450 2625,1450 2625,2250 3365,2250 3545,2430 3545,2435 4015,2435 4015,2370 4015,50 3830,50 50,50
2-VC0 on Signal Layer 2 "Signal Layer 1-No Net 1" (solid, remove dead copper, pour order 28): 50,4500 2250,4500 2250,3625 2650,3625 2650,4500 3400,4500 3400,2445 3255,2300 3250,2300 2600,2300 2600,1475 2251.46,1475 2250,1476.46 2250,2300 50,2300
3-VC0 on Signal Layer 2 "Signal Layer 1-No Net" (solid, remove dead copper, pour order 27): 50,6950 3390,6950 3400,6940 3400,4575 2625,4575 2625,3650 2276.77,3650 2276.77,4575 50,4575

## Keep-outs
Keep-Out Layer:
  text ".Layer_Name" at 577,-858.49 h60

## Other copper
Top Layer:
  region net 2-VC0: 3155,2290 3170,2305 3095,2305 3110,2290
  region net 1-VC0: 3115,2266.9 3094.6,2246.5 3180.4,2246.5 3160,2266.9
  region net 3-VC0: 312,4747 384,4747 384,4600 312,4600
  region net 1-VC0: 293,911 367,911 367,757 293,757
  region net NetQ1_3: 1558.43,1965 1558.43,2095 1475,2095 1475,2070 1450,2045 1319,2045 1319,1965
  region net 3-CELL1: 865,4818 918,4818 933,4833 1065,4833 1065,4967 990,4967 990,4990 1365,4990 1410,5035 1530,5035 1530,5100 1390,5100 1370,5080 1290,5080 1265,5055 1085,5055 1085,5115 945,5115 927,5133 865,5133
  region net NetQ4_1: 1287,1283 1210,1283 1210,1420 1325,1420 1370,1465 1461,1465 1461,1345 1415,1345 1390,1370 1325,1370 1287,1332
  region net NetD3_2: 3060,5320 3060,5175 3135,5175 3135,5320 3060,5320
  region net 1-CELL1: 1470,755 1540,755 1540,689 1470,689
  region net 3-CELL2: 865,5168 918,5168 933,5183 1065,5183 1065,5317 990,5317 990,5340 1365,5340 1410,5385 1530,5385 1530,5454 1394,5454 1370,5430 1290,5430 1265,5405 1085,5405 1085,5466 944,5466 926,5484 865,5484
  region net 3-CELL1: 1470,5285 1535,5285 1535,5360 1470,5360 1470,5285
  region net 2-CELL2: 1470,3430 1540,3430 1540,3364 1470,3364
  region net NetQ18_1: 1165,5880 1262,5880 1262,5950 1395,5950 1415,5930 1461,5930 1461,6055 1420,6055 1381.27,6016.27 1165,6016.27
  region net NetD2_2: 3060,3020 3060,2905 3070,2895 3070,2825 3110,2825 3110,3020 3060,3020
  region net 1-CELL2: 1470,1105 1540,1105 1540,1039 1470,1039
  region net NetQ19_1: 1165,5534 1259,5534 1280,5555 1280,5610 1395,5610 1415,5590 1461,5590 1461,5715 1430,5715 1385,5670 1165,5670
  region net NetQ22_3: 1300,4815 1390,4815 1415,4790 1535,4790 1535,4915 1470,4915 1470,4875 1460,4865 1405,4865 1385,4885 1310,4885 1300,4875
  region net NetQ11_3: 1415.76,3564.24 1557.98,3564.24 1557.98,3695 1485,3695 1474,3695 1474,3659 1465,3650 1405,3650 1395,3660 1395,3670 1380,3685 1319,3685 1319,3600 1380,3600
  region net 3-VC0: 2990,5180 3045,5180 3045,5250 2990,5250 2990,5180
  region net 3-CELL4: 864,5866 931,5866 945,5880 1075,5880 1075,6015.91 1000,6015.91 1000,6035 1360,6035 1405,6080 1540,6080 1540,6145 1400,6145 1380,6125 1300,6125 1275,6100 1090,6100 1090,6160 955,6160 932,6183 864,6183
  region net NetD4_4: 3570,2270 3570,2235 3590,2215 3590,2111 3616,2111 3635,2130 3705,2130 3705,2170 3660,2170 3650,2180 3650,2205 3600,2255 3600,2270
  region net NetQ6_1: 1210,1070 1210,935 1268,935 1268,973 1325,1030 1385,1030 1415,1000 1415,995 1461,995 1461,1105 1385,1105 1350,1070
  region net 3-CELL3: 1470,5980 1535,5980 1535,6055 1470,6055 1470,5980
  region net 3-VC0: 865,4783 942,4783 965,4760 1085,4760 1085,4695 1295,4695 1323,4723 1375,4723 1417,4765 1540,4765 1540,4635 865,4635
  region net 1-VC0: 3120,965 3160,965 3160,1070 3120,1070 3120,965
  region net NetQ8_1: 1211,365 1211,232 1267,232 1288,253 1288,315 1385,315 1405,295 1405,270 1461,270 1461,380 1405,380 1390,365
  region net 2-CELL6: 1030,4306 863.3,4306 863.3,4460 1030,4460
  region net 2-CELL1: 863.3,2874 863.3,2557 1029.39,2557 1029.39,2708.33 969.39,2708.33 969.39,2723.33 1364.39,2723.33 1409.39,2768.33 1557.08,2768.33 1557.08,2828.33 1284.39,2828.33 1244.39,2788.33 1085,2788.33 1085,2853.33 939.39,2853.33 918.72,2874
  region net NetQ17_3: 1300,6215 1390,6215 1420,6185 1515,6185 1535,6185 1535,6310 1470,6310 1470,6270 1460,6260 1405,6260 1385,6280 1310,6280 1300,6270
  region net NetQ6_3: 1319,895 1558.43,895 1558.43,1020 1485,1020 1470,1005 1470,990 1460,980 1410,980 1393,997 1319,997
  region net NetQ13_3: 1407,3223 1557.98,3223 1557.98,3345 1475,3345 1475,3310 1465,3300 1405,3300 1395,3310 1395,3313 1373,3335 1319,3335 1319,3250 1380,3250
  region net 2-CELL1: 1470,3055 1540,3055 1540,2989 1470,2989
  region net NetQ18_3: 1300,5865 1375,5865 1405,5835 1515,5835 1535,5835 1535,5960 1470,5960 1470,5920 1460,5910 1405,5910 1385,5930 1310,5930 1300,5920
  region net NetQ10_3: 1417,3913 1558.47,3913 1558.47,4045 1475,4045 1475,4010 1465,4000 1405,4000 1395,4010 1380,4025 1319,4025 1319,3950 1380,3950
  region net NetQ4_3: 1319,1245 1557.98,1245 1557.98,1370 1475,1370 1475,1335 1460,1320 1415,1320 1397,1338 1319,1338
  region net NetQ14_1: 1263,2923 1210,2923 1210,3065 1461,3065 1461,2945 1425,2945 1400,2970 1310,2970
  region net 2-CELL3: 1470,3780 1540,3780 1540,3714 1470,3714
  region net 1-CELL5: 1470,2180 1550,2180 1550,2113 1470,2113
  region net 2-CELL3: 863.3,3588 863.3,3257 1032.2,3257 1032.2,3420.07 972.2,3420.07 972.2,3435.07 1367.2,3435.07 1412.2,3480.07 1553,3480.07 1553,3545 1319,3545 1268,3494 1085,3494 1085,3565.07 948.93,3565.07 926,3588
  region net NetQ8_3: 1319,211 1355,175 1558.88,175 1558.88,295 1480,295 1470,285 1470,255 1460,245 1410,245 1375,280 1375,295 1319,295
  region net NetQ9_1: 1268,4323 1210,4323 1210,4455 1461,4455 1461,4340 1430,4340 1370,4400 1320,4400 1268,4348
  region net 3-VC0: 1470,4933 1535,4933 1535,5010 1470,5010
  region net 1-CELL5: 865,1937 865,1618 1035,1618 1035,1770 980,1770 980,1790 1303.63,1790 1378.63,1865 1558.43,1865 1558.43,1945 1330,1945 1240,1855 1085,1855 1085,1937
  region net NetQ21_3: 1300,5167 1393,5167 1420,5140 1515,5140 1535,5140 1535,5265 1470,5265 1470,5225 1460,5215 1405,5215 1385,5235 1310,5235 1300,5225
  region net NetQ16_1: 1165,6580 1265,6580 1280,6595 1280,6650 1395,6650 1415,6630 1461,6630 1461,6755 1412.5,6755 1373.5,6716 1165,6716
  region net NetQ11_1: 1273,3622 1210,3622 1210,3760 1375,3760 1405,3790 1461,3790 1461,3670 1415,3670 1415,3690 1390,3715 1320,3715 1273,3668
  region net 3-CELL2: 1470,5628 1535,5628 1535,5710 1470,5710
  region net NetQ17_1: 1165,6230 1265,6230 1265,6300 1395,6300 1415,6280 1461,6280 1461,6405 1420,6405 1381,6366 1165,6366
  region net 3-CELL3: 864,5517 927,5517 945,5535 1075,5535 1075,5665 1000,5665 1000,5690 1360,5690 1405,5735 1540,5735 1540,5800 1400,5800 1380,5780 1300,5780 1275,5755 1090,5755 1090,5815 955,5815 936,5834 864,5834
  region net NetC120_1: 3580,2185 3540,2185 3540,2140 3520,2120 3455,2120 3455,2075 3495,2075 3510,2060 3580,2060
  region net 1-CELL3: 1470,1455 1540,1455 1540,1389 1470,1389
  region net 2-CELL5: 863.3,4275 863.3,3955 1035,3955 1035,4115 975,4115 975,4130 1370,4130 1415,4175 1558.06,4175 1558.06,4235 1290,4235 1250,4195 1085,4195 1085,4260 945,4260 930,4275
  region net 1-VC0: 1470,380 1540,380 1540,311 1470,311
  region net NetQ7_1: 1209,583 1209,715 1340,715 1390,765 1461,765 1461,645 1415,645 1395,665 1320,665 1265,610 1265,583
  region net NetQ23_4: 4395,640 4450,640 4450,710 4395,710 4395,640
  region net 3-CELL6: 863,6566 1085,6566 1085,6730 863,6730
  region net NetD1_2: 3065,865 3065,750 3075,740 3075,660 3120,660 3120,865 3065,865
  region net 1-CELL6: 1035,2140 866,2140 865,2139 865,1960 930,1960 975,2005 1035,2005
  region net NetQ7_3: 1319,545 1558.43,545 1558.43,670 1485,670 1470,655 1470,640 1455,625 1410,625 1400,635 1319,635
  region net 2-VC0: 3045,2965 2990,2965 2990,2905 3045,2905 3045,2965
  region net NetQ23_4: 4395,315 4450,315 4450,380 4395,380 4395,315
  region net 2-VC0: 863.3,2525 863.3,2340 1557.98,2340 1557.98,2420 1130,2420 1085,2465 1085,2500 944,2500 919,2525
  region net NetQ9_3: 1377.47,4257.53 1557.82,4257.53 1557.82,4365 1475,4365 1475,4335 1465,4325 1415,4325 1380,4360 1319,4360 1319,4300 1335,4300
  region net 2-VC0: 285,3000.84 360,3000.84 360,2843.16 285,2843.16
  region net 3-CELL4: 1470,6330 1535,6330 1535,6405 1470,6405 1470,6330
  region net 2-CELL2: 863.3,3223 863.3,2907 1040.6,2907 1040.6,3069.81 980.6,3069.81 980.6,3084.81 1375.6,3084.81 1420.6,3129.81 1557.98,3129.81 1557.98,3204 1309.79,3204 1255.6,3149.81 1090.6,3149.81 1090.6,3214.81 950.6,3214.81 942.41,3223
  region net NetQ1_1: 1269,2010 1205,2010 1205,2190 1461,2190 1461,2070 1310,2070 1269,2029
  region net NetQ14_3: 1319,2935 1319,2845 1556.63,2845 1556.63,2970 1475,2970 1475,2940 1460,2925 1410,2925 1400,2935
  region net 2-VC0: 1470,2655 1540,2655 1540,2584 1470,2584
  region net NetQ3_1: 1280,1630 1205,1630 1205,1765 1320,1765 1365,1810 1461,1810 1461,1690 1410,1690 1385,1715 1311,1715 1280,1684
  region net NetQ16_3: 1300,6565 1390,6565 1420,6535 1515,6535 1535,6535 1535,6660 1470,6660 1470,6621 1459,6610 1405,6610 1385,6630 1310,6630 1300,6620
  region net 1-CELL2: 863.3,910 863.3,567 1035,567 1035,720 980,720 980,735 1335,735 1410.25,810.25 1558.43,810.25 1558.43,875.91 1340.91,875.91 1245,780 1090,780 1090,855 973,855 918,910
  region net 1-VC0: 3050,750 2985,750 2985,815 3050,815 3050,750
  region net NetQ22_1: 1165,4835 1265,4835 1280,4850 1280,4905 1395,4905 1415,4885 1461,4885 1461,5010 1412.5,5010 1367.5,4965 1165,4965
  region net 2-CELL4: 1470,4130 1540,4130 1540,4065 1470,4065
  region net NetQ15_1: 1215,2575 1215,2700 1461,2700 1461,2545 1415,2545 1385,2575
  region net 3-CELL5: 1470,6678 1535,6678 1535,6755 1470,6755
  region net 1-CELL4: 865,1585 865,1266 1030,1266 1030,1420 985,1420 985,1435 1305,1435 1380,1510 1557.08,1510 1557.08,1570 1325,1570 1240,1485 1085,1485 1085,1570 945,1570 930,1585
  region net NetQ24_1: 4380,595 4265,595 4246,576 4196,576 4196,625 4276,705 4380,705
  region net NetQ3_3: 1319,1595 1557.98,1595 1557.98,1720 1485,1720 1470,1705 1470,1685 1460,1675 1390,1675 1380,1685 1319,1685
  region net NetQ10_1: 1281,3973 1210,3973 1210,4110 1380,4110 1410,4140 1461,4140 1461,4020 1415,4020 1390,4045 1308,4045 1281,4018
  region net 1-CELL4: 1470,1805 1545,1805 1545,1739 1470,1739
  region net NetQ21_1: 1165,5185 1265,5185 1280,5200 1280,5255 1395,5255 1415,5235 1461,5235 1461,5360 1412.5,5360 1367.5,5315 1165,5315
  region net 2-CELL4: 863.3,3924.73 863.3,3620 1035,3620 1035,3764.73 975,3764.73 975,3779.73 1370,3779.73 1415,3824.73 1557.98,3824.73 1557.98,3888 1293.27,3888 1250,3844.73 1085,3844.73 1085,3911 943.73,3911 930,3924.73
  region net 1-VC0: 863.3,205 863.3,55 1560,55 1560,153 1319,153 1256,90 1147,90 1084,153 997,153 945,205
  region net 1-CELL1: 863.3,535 863.3,245 1030,245 1030,370 990,370 990,385 1335,385 1405,455 1557.98,455 1557.98,525 1335,525 1240,430 1100,430 1100,505 960,505 930,535
  region net NetQ15_3: 1319,2545 1319,2440 1557.98,2440 1557.98,2565 1475,2565 1475,2535 1460,2520 1410,2520 1385,2545
  region net 1-CELL3: 865,1234 865,940 1035,940 1035,1070 980,1070 980,1085 1340,1085 1420,1165 1557.98,1165 1557.98,1230 1340,1230 1245,1135 1085,1135 1085,1210 945,1210 921,1234
  region net NetQ19_3: 1300,5515 1385,5515 1415,5485 1515,5485 1535,5485 1535,5610 1470,5610 1470,5570 1460,5560 1405,5560 1385,5580 1310,5580 1300,5570
  region net NetQ23_1: 4197,426 4197,330 4265,330 4330,265 4380,265 4380,338 4380,380 4338,380 4292,426
  region net 2-CELL5: 1475,4455 1540,4455 1540,4383 1475,4383
  region net 3-CELL5: 864,6216 931,6216 945,6230 1075,6230 1075,6365.64 1000,6365.64 1000,6385 1365,6385 1410,6430 1540,6430 1540,6505 1410,6505 1380,6475 1300,6475 1275,6450 1090,6450 1090,6510 955,6510 932,6533 864,6533
  region net NetQ2_1: 3105,1035 3040,1035 3000,995 2970,995 2970,955 3000,955 3040,915 3105,915 3105,1035
  region net NetQ13_1: 1266,3272 1210,3272 1210,3410 1365,3410 1395,3440 1461,3440 1461,3320 1420,3320 1420,3335 1390,3365 1315,3365 1266,3316
  region net 1-VC0: 2153.15,1195.35 2153.13,1195.37 2087.43,1195.37 2058.09,1166.03 2058.09,1148.01 2152.46,1148.01 2153.15,1147.32
  region net 2-VC0: 2153.15,3365.35 2085.68,3365.29 2057.01,3336.62 2057.01,3318.86 2153.15,3318.86
  region net 3-VC0: 2105.12,5615.34 2083.17,5615.34 2048.48,5580.65 2048.49,5567.34 2049.37,5567.34 2153.15,5567.32 2153.15,5615.35
  region net 1-VC0: 710,2270 683.81,2243.81 781.19,2243.81 755,2270
  region net 2-VC0: 225,2290 240,2305 165,2305 180,2290
  region net 2-VC0: 755,2290 770,2305 695,2305 710,2290
  region net 3-VC0: 220,4565 235,4580 165,4580 180,4565
  region net 3-VC0: 657.5,4557.5 680,4580 590,4580 612.5,4557.5
  region net 3-VC0: 2065,4565 2080,4580 1975,4580 1990,4565
  region net 3-VC0: 3175,4555 3197.43,4577.43 3107.57,4577.43 3130,4555
  region net 2-VC0: 3135,4531.9 3098.1,4495 3216.9,4495 3180,4531.9
  region net 2-VC0: 612.5,4537.5 570.02,4495.02 699.98,4495.02 657.5,4537.5
  text ".Layer_Name" at 577,-858.49 h60
Signal Layer 1:
  text ".Layer_Name" at 577,-858.49 h60
Signal Layer 2:
  text ".Layer_Name" at 577,-858.49 h60
Bottom Layer:
  region net 1-CELL6: 865,2080 865,1965 940,1965 940,2080 865,2080
  text ".Layer_Name" at 577,-858.49 h60

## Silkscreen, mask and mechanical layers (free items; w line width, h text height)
Top Overlay:
  lines w5: 1615,3679 1655,3639 ; 1620,5700 1642,5722 1642,5733 1655,5746 ; 1624,3637 1642,3619 1642,3593 1649,3586 1649,3559 1656,3552 ; 1630,5655 1660,5684
  lines w6: 1626,5936 1627,5936 1644,5919 1644,5867 1660,5851 ; 2563,626 2581,608 2590,608
  lines w8: 3010,5035 3030,5035 ; 3020,2710 3040,2710 ; 3025,560 3045,560 ; 3065,5005 3065,5035 ; 3065,5065 3065,5035 ; 3075,2680 3075,2710 ; 3075,2740 3075,2710 ; 3080,530 3080,560 ; 3080,590 3080,560 ; 3100,5035 3065,5035 ; 3110,2710 3075,2710 ; 3115,560 3080,560 ; 4019.6,58.56 4019.6,1033.56 ; 4019.6,1233.56 4019.6,2833.56 ; 4049.6,58.56 4049.6,1033.56 ; 4070,1235 4070,2835 ; 4635,3005 4635,3685 ; 3065,5035 3035,5065 3035,5005 3065,5035 ; 3075,2710 3045,2740 3045,2680 3075,2710 ; 3080,560 3050,590 3050,530 3080,560
  lines w10: 1515,2255 820,2255 820,40 2065,40 ; 1525,4505 1480,4505 820,4505 820,2295 1515,2295 1870,2295 ; 1700,6895 818.3,6895 818.3,4570.8 1919.2,4570.8 ; 1885,6895 2055,6895 ; 2065,2255 2235,2255 ; 2065,2295 3035,2295 ; 2105,4500 3050,4500 ; 2105,4575 3050,4575 ; 2590,2255 3035,2255 ; 2920,40 3400,40 3400,1080 ; 3020,6900 3400,6900 3400,4575.8 3205.8,4575.8 ; 3178.89,2250 3200,2250 3400,2250 3400,2005 ; 3180,2295 3399.2,2295 ; 3205,4500 3400,4500 3400,2445 3400,2294.2 ; 4965,40 3425,40 3425,3005 4630,3005 4630,3690 4965,3690 ; 4000,4015 4000,4665 4800,4665 4800,4015 4000,4015 ; 4000,4880 4000,5530 4800,5530 4800,4880 4000,4880 ; 4000,5750 4000,6425 4800,6425 4800,5750 4000,5750
  text "2" at 2062.56,6837.64 h25
  text "10" at 2917.27,6834.64 h25
  text "9" at 2921.77,6735.68 h25
  text "1" at 2070.06,6720.68 h25
  text "Bq76PL536AQ1EVM763" at 3618,6549 h100
  text "PWR763A" at 4195,6440 h100
  text "TS2+" at 2190,6340 h45
  text "TS2-" at 1730,6335 h45
  text "CAUTION" at 245,6260 h100
  text "HIGH VOLTAGE" at 117,6149 h100
  text "JUMPERS" at 130,5995 h50
  text "THERMISTORS CIRCUIT 3" at 4065,5980 h40
  text "THERMISTORS" at 4145,5790 h50
  text "1" at 195.7,5776.01 h50
  text "CELL 18+" at 292,5658 h35
  text "CELL 17+" at 291,5509 h35
  text "CELL 16+" at 291,5359 h35
  text "CELL 15+" at 290,5210 h35
  text "THERMISTORS CIRCUIT 2" at 4060,5070 h40
  text "TS1-" at 1785,5065 h45
  text "CELL 14+" at 291,5058 h35
  text "TS1+" at 1780,4910 h45
  text "THERMISTORS" at 4140,4910 h50
  text "CELL 13+" at 293,4908 h35
  text "CIRCUIT 3" at 2930,4720 h50
  text "CELL 13-" at 625,4695 h35
  text "7" at 182.2,4643.89 h50
  text "TIPMM-21246-01" at 3639.73,4570.85 h50 r90
  text "JUMPERS" at 115,4390 h50
  text "TS2+" at 1845,4240 h45
  text "THERMISTORS CIRCUIT 1" at 4065,4195 h40
  text "TS2-" at 1850,4170 h45
  text "CELL 12+" at 625,4080 h35
  text "THERMISTORS" at 4170,4045 h50
  text "1" at 191.38,4030.83 h50
  text "CELL 12+" at 290,3930 h35
  text "CELL 11+" at 290,3765 h35
  text "10" at 4755.64,3747.19 h37.5
  text "CELL 10+" at 290,3615 h35
  text "CELL 9+" at 290,3465 h35
  text "CELL 8+" at 290,3315 h35
  text "CELL 7+" at 290,3165 h35
  text "TIPMM-21246-01" at 3593,3040 h50
  text "CELL 7-" at 440,2995 h35
  text "7" at 185.2,2904.48 h50
  text "TS1-" at 1860,2880 h45
  text "ISOLATED COMMUNICATIONS INTERFACE" at 3520,2870 h35
  text "TS1+" at 1865,2775 h45
  text "COMMS" at 3720,2515 h50
  text "CIRCUIT 2" at 2935,2470 h50
  text "JUMPERS" at 105,2140 h50
  text "TS2+" at 1905,2005 h45
  text "1" at 197.2,1994.3 h50
  text "2" at 3324,1985 h37.5
  text "1" at 3086,1982 h37.5
  text "CELL 6+" at 620,1915 h35
  text "TS2-" at 1905,1895 h45
  text "CELL 6+" at 267,1793 h35
  text "1" at 4635,1650 h37.5
  text "1" at 4940,1650 h37.5
  text "CELL 5+" at 267,1643 h35
  text "CELL 4+" at 268,1498 h35
  text "CELL 3+" at 269,1350 h35
  text "CELL 2+" at 269,1201 h35
  text "10" at 3445,1160 h37.5
  text "3.3V" at 3985,1160 h35
  text "9" at 3010,1155 h37.5
  text "H" at 2700,1110 h37.5
  text "5.0V" at 3985,1095 h35
  text "CELL 1+" at 269,1051 h35
  text "CELL 1-" at 420,880 h35
  text "S" at 2685,865 h37.5
  text "7" at 192.7,860.68 h50
  text "9" at 4701.34,744.9 h37.5
  text "10" at 4873,744 h37.5
  text "TS1-" at 1723.17,694.09 h45
  text "TS1+" at 2191.7,602.68 h45
  text "10" at 2930,295 h25
  text "2" at 2010,285 h25
  text "CIRCUIT 1" at 2975,155 h50
  text "9" at 2945,95 h25
  text "1" at 2010,85 h25
  text ".Layer_Name" at 577,-858.49 h60
Bottom Overlay:
  text ".Layer_Name" at 577,-858.49 h60
Top Paste:
  text ".Layer_Name" at 577,-858.49 h60
Bottom Paste:
  text ".Layer_Name" at 577,-858.49 h60
Top Solder:
  the board outline again, w30
  text ".Layer_Name" at 577,-858.49 h60
  text ".Layer_Name" at 577,-858.49 h60
Bottom Solder:
  the board outline again, w30
  text ".Layer_Name" at 577,-858.49 h60
Drill Guide:
  text ".Layer_Name" at 577,-858.49 h60
M1 Board Outline:
  lines w10: 5000,40 5000,3690 ; 0,0 5000,0 5000,7000 0,7000 0,0
  text ".Layer_Name" at 577,-858.49 h60
M2 Board Dimensions:
  rectangle: 125,-400 500,-275
  rectangle: 0,-275 125,-150
  lines w7: 0,-275 1000,-275 ; 125,-400 125,-150 ; 250,-400 250,-150 ; 500,-400 500,-150 ; 750,-400 750,-150 ; 0,-400 0,-150 1000,-150 1000,-400 0,-400
  text ".Layer_Name" at 577,-858.49 h60
M3 3D STEP Top:
  text ".Layer_Name" at 577,-858.49 h60
M4 3D STEP Bottom:
  text ".Layer_Name" at 577,-858.49 h60
M5 Assembly Top:
  lines w10: -292,-930.17 6308,-930.17 ; -292,-726.83 6310,-726.83 ; -292,-523.5 -292,-1133.5 3713,-1133.5 6310,-1133.5 6310,-523.5 -291.5,-523.5 -291.5,-1133.5 1284,-1133.5 ; 2173,-1133.5 2173,-523.5 ; 3440,-726.83 3440,-523.5 ; 4280,-726.83 4280,-523.5 ; 4902,-1140 4902,-937.17
  text "COMPONENTS MARKED 'DNP' SHOULD NOT BE POPULATED." at 1153.5,-318.5 h60
  text "ASSEMBLY VARIANT:" at 1153,-434 h60
  text ".VariantName" at 2189,-434 h60
  text "PCB VIEWED FROM TOP SIDE" at -228.5,-655.67 h60
  text "BOARD #:" at 2248,-655.67 h60
  text ".PRJ_Number" at 2793.5,-655.67 h60
  text "REV:" at 3638,-655.67 h60
  text ".PCB_Rev" at 3929.5,-655.67 h60
  text "SVN REV:" at 4476,-655.67 h60
  text ".VersionControl_RevNumber" at 4982,-655.67 h60
  text "TID #:" at 2248,-859 h60
  text ".TID" at 2793.5,-859 h60
  text "PLOT NAME =" at -228.5,-1064.34 h60
  text ".plot_File_Name" at 577,-1064.34 h60
  text "GENERATED    :" at 2250,-1064.34 h60
  text ".Print_Date" at 3119.5,-1064.34 h60
  text ".Print_Time" at 3848.5,-1064.34 h60
  text "TEXAS INSTRUMENTS" at 5113,-1064.34 h60
M6 Assembly Bottom:
  lines w10: -292.5,-727.33 6309.5,-727.33 ; -290.5,-930.67 6309.5,-930.67 ; 1115.5,-1140.5 1115.5,-937.67 ; 1737.5,-727.33 1737.5,-524 ; 2577.5,-727.33 2577.5,-524 ; 3844.5,-1134 3844.5,-524 ; 4733.5,-1134 6309,-1134 6309,-524 -292.5,-524 -292.5,-1134 2304.5,-1134 6309.5,-1134 6309.5,-524
  text "COMPONENTS MARKED 'DNP' SHOULD NOT BE POPULATED." at 6102,-318 h60
  text ".VariantName" at 5058,-434 h60
  text "ASSEMBLY VARIANT:" at 6097,-434 h60
  text ".VersionControl_RevNumber" at 1035.5,-656.17 h60
  text "SVN REV:" at 1541.5,-656.17 h60
  text ".PCB_Rev" at 2088,-656.17 h60
  text "REV:" at 2379.5,-656.17 h60
  text ".PRJ_Number" at 3224,-656.17 h60
  text "BOARD #:" at 3769.5,-656.17 h60
  text "PCB VIEWED FROM BOTTOM SIDE" at 6246,-656.17 h60
  text ".PRJ_Number" at 3224,-859.5 h60
  text "TID #:" at 3769.5,-859.5 h60
  text "TEXAS INSTRUMENTS" at 904.5,-1064.84 h60
  text ".Print_Time" at 2169,-1064.84 h60
  text ".Print_Date" at 2898,-1064.84 h60
  text "GENERATED    :" at 3767.5,-1064.84 h60
  text ".plot_File_Name" at 5440.5,-1064.84 h60
  text "PLOT NAME =" at 6246,-1064.84 h60
M9 Title Sheet:
  drawing of 57 lines, arcs and shapes, not listed
  text "1" at 739.84,8036.5 h70
  text "2" at 3235.5,8036.5 h70
  text "3" at 5724.84,8036.5 h70
  text "4" at 8231.51,8036.5 h70
  text "5" at 10730.5,8036.5 h70
  text "6" at 13235.5,8036.5 h70
  text "A" at -416.5,6893.5 h70
  text "A" at 14383.5,6893.5 h70
  text "B" at -416.5,4513.5 h70
  text "B" at 14383.5,4513.5 h70
  text "C" at -416.5,2138.5 h70
  text "C" at 14383.5,2138.5 h70
  text "PROJECT TITLE:" at 11343.5,277.5 h45
  text ".PRJ_Title" at 11393.5,144.17 h60
  text "DESIGNED FOR:" at 11343.5,-23.5 h45
  text ".PRJ_Customer" at 11393.5,-163.5 h60
  text "D" at -416.5,-231.5 h70
  text "D" at 14383.5,-231.5 h70
  text "FILE NAME:" at 11343.5,-323.5 h45
  text ".PCB_File_Name_No_Path" at 11393.5,-443.5 h60
  text "Texas Instruments (TI) and/or its licensors do not warrant the accuracy or completeness of this specification" at 6374,-605.34 h45
  text "ENGINEER:" at 11343.5,-613.5 h45
  text "LAYOUT BY:" at 12848.5,-613.5 h45
  text "or any information contained therein. TI and/or its licensors do not warrant that this design will meet" at 6329.01,-718 h45
  text ".PRJ_Engineer" at 11393.5,-768.49 h60
  text ".PCB_Layout" at 12899,-768.49 h60
  text "the specifications, will be suitable for your application or fit for any particular purpose, or will operate in" at 6329.01,-830.67 h45
  text ".Layer_Name" at 577,-858.49 h60
  text "ALTIUM DESIGNER VERSION:" at 12848.5,-923.5 h45
  text "an implementation. TI and/or its licensors do not warrant that the design is production worthy. You should" at 6329.01,-943.33 h45
  text "completely validate and test your design implementation to confirm the system functionality for your application." at 6374,-1056 h45
  text ".print_Scale" at 11393.5,-1056.83 h70
  text ".Application_BuildNumber" at 12899,-1056.83 h70
  text "1" at 739.84,-1263.5 h70
  text "2" at 3235.5,-1263.5 h70
  text "3" at 5724.84,-1263.5 h70
  text "4" at 8231.51,-1263.5 h70
  text "5" at 10730.5,-1263.5 h70
  text "6" at 13235.5,-1263.5 h70
M10 Fab Notes:
  drawing of 185 lines, arcs and shapes, not listed
  text "DESIGN INFORMATION" at 12381.02,5910 h60
  text "MIN. TRACK WIDTH:" at 11736.46,5730 h60
  text "8" at 12832.7,5730 h60
  text "MIL" at 12987.46,5730 h60
  text "MIN. CLEARANCE:" at 11736.46,5598 h60
  text "0.2" at 12772.7,5598 h60
  text "mm" at 12987.46,5598 h60
  text "MIN. VIA PAD SIZE:" at 11736.46,5466 h60
  text "24" at 12802.71,5466 h60
  text "MIL" at 12987.46,5466 h60
  text "0.05mm (2MIL)" at 12431.46,5324.29 h60
  text "MINIMUM ANNULAR RING" at 11407.23,5320 h60
  text "EXTERNAL" at 13139.46,5320 h60
  text "PER" at 11607.23,5202 h60
  text "IPC-D-275 CLASS 2 LEVEL C" at 11827.23,5202 h60
  text "MIL, HOLES" at 13315.46,5089.71 h60
  text "+/-" at 12923,5089 h60
  text "+/-" at 13777,5089 h60
  text "REGISTRATION TOLERANCES:" at 11407.23,5084 h60
  text "METAL" at 12607,5084 h60
  text "5" at 13183.2,5084 h60
  text "3" at 14016.2,5084 h60
  text "MIL" at 14132.46,5084 h60
  text "MATERIAL:" at 11332.46,4874.54 h60
  text "FR-4 High Tg" at 12318.9,4734.21 h60
  text "FR-408" at 11753.46,4725.64 h60
  text "X" at 12165.46,4725.64 h60
  text "OTHER" at 13241.46,4725.64 h60
  text "62 MIL (1.6mm) +/-10%" at 12073.56,4562.92 h60
  text "X" at 13231,4561 h60
  text "THICKNESS:" at 11407.23,4558.64 h60
  text "OTHER" at 13358.46,4558.64 h60
  text "TOLERANCE:" at 11407.23,4400.64 h60
  text "X" at 12246.53,4400.64 h60
  text "ANSI IPC-6012 TYPE 3 CLASS 2" at 12433.48,4400.64 h60
  text "OTHER +/-" at 12433.46,4244.64 h60
  text "BOW & TWIST:" at 11407.23,4087.64 h60
  text "X" at 12246.53,4087.64 h60
  text "ANSI IPC-6012 TYPE 3 CLASS 2" at 12433.48,4087.64 h60
  text "OTHER +/-" at 12433.46,3929.13 h60
  text "DRILLING:" at 11332.46,3790.64 h60
  text "REFERENCE:" at 11407.23,3673.64 h60
  text "X" at 12055.46,3673.64 h60
  text "AS SHOWN" at 12242.46,3673.64 h60
  text "X" at 12956.46,3673.64 h60
  text "NC_DRILL FILES" at 13093.46,3673.64 h60
  text "X" at 12760,3523 h60
  text "PTH MIN COPPER THICKNESS:" at 11407.23,3515.64 h60
  text "1MIL" at 12894.46,3515.64 h60
  text "OTHER" at 13391.46,3515.64 h60
  text "BOARD FINISH:" at 11332.46,3356.64 h60
  text "SILKSCREEN:" at 11487.68,3238.64 h60
  text "X" at 12436.46,3238.64 h60
  text "TOP" at 12562.46,3238.64 h60
  text "BOTTOM" at 13073.46,3238.64 h60
  text "SILKSCREEN COLOR:" at 11487.68,3071.64 h60
  text "X" at 12435.42,3071.64 h60
  text "WHITE" at 12562.46,3071.64 h60
  text "OTHER" at 13073.46,3071.64 h60
  text "SOLDER RESIST COLOR:" at 11487.68,2901.64 h60
  text "X" at 12055.42,2742.44 h60
  text "GREEN" at 12182.46,2742.44 h60
  text "BLUE" at 12773.46,2742.44 h60
  text "OTHER" at 13311.46,2742.44 h60
  text "IMMERSION GOLD (ENIG)" at 12393.46,2553.92 h60
  text "ENEPIG" at 13731,2550.64 h60
  text "SURFACE FINISH:" at 11332.46,2549.64 h60
  text "X" at 12206.51,2549.64 h60
  text "IMM. TIN/SILVER OR EQUIV" at 11662,2392.64 h60
  text "OTHER" at 13093.46,2392.64 h60
  text "ARRAY/PANEL:" at 11332.46,2213.64 h60
  text "CUT AND TRIM PER MECH LAYER 1" at 12393.46,2209.35 h60
  text "N.C. ROUTE" at 12393.46,2057.64 h60
  text "X" at 13072.46,2057.64 h60
  text "V. SCORE" at 13259.46,2057.64 h60
  text "CERTIFICATION:" at 11332.46,1920.64 h60
  text "MATERIALS AND WORKMANSHIP FOR ALL PCBS" at 12057.46,1920.64 h60
  text "TO MEET OR EXCEED THE REQUIREMENTS OF:" at 12057.46,1822.64 h60
  text "X" at 11683.96,1686.13 h60
  text "ANSI IPC-A-600F CLASS ->" at 11822.96,1686.13 h60
  text "X" at 13462.02,1686.13 h60
  text "2" at 13580.96,1686.14 h60
  text "1" at 13265.96,1684.64 h60
  text "3" at 13934.96,1684.64 h60
  text "X" at 11686.02,1526.64 h60
  text "UL 94V-0" at 11822.96,1526.64 h60
  text "X" at 12498.02,1526.64 h60
  text "RoHS" at 12634.96,1526.64 h60
  text "OTHER" at 13279.36,1526.64 h60
  text "PER ORDER" at 13676.42,1526.64 h60
  text "ADDITIONAL REQUIREMENTS:" at 11332.46,1385.64 h60
  text "MICROSECTION:" at 11407.23,1270.64 h60
  text "YES" at 12312.96,1270.64 h60
  text "REQUIRED" at 13174.46,1114.49 h60
  text "BARE BOARD ELEC. TEST:" at 11407.23,1111.64 h60
  text "NONE" at 12712.96,1111.64 h60
  text "X" at 13047.46,1111.64 h60
  text "PER ORDER" at 13766.46,1111.64 h60
  text "MANUFACTURER'S UL:" at 11407.23,954.64 h60
  text "RAIL" at 12572.96,950.35 h60
  text "METAL" at 13064.77,950.35 h60
  text "X" at 13440,950 h60
  text "SILK" at 13576.46,950.35 h60
  text ".Layer_Name" at 577,-858.49 h60
M11 Gerber Information:
  lines w10: -292,-930.17 6308,-930.17 ; -292,-726.83 6310,-726.83 ; -292,-523.5 -292,-1133.5 3713,-1133.5 6310,-1133.5 6310,-523.5 -291.5,-523.5 -291.5,-1133.5 1284,-1133.5 ; 2173,-1133.5 2173,-523.5 ; 3440,-726.83 3440,-523.5 ; 4280,-726.83 4280,-523.5 ; 4902,-1140 4902,-937.17
  text "ALL ARTWORK VIEWED FROM TOP SIDE" at -228.5,-655.67 h60
  text "BOARD #:" at 2248,-655.67 h60
  text ".PRJ_Number" at 2793.5,-655.67 h60
  text "REV:" at 3638,-655.67 h60
  text ".PCB_Rev" at 3929.5,-655.67 h60
  text "SVN REV:" at 4476,-655.67 h60
  text ".VersionControl_RevNumber" at 4982,-655.67 h60
  text "LAYER NAME =" at -228.5,-858.49 h60
  text "TID #:" at 2248,-859 h60
  text ".TID" at 2793.5,-859 h60
  text "PLOT NAME =" at -228.5,-1064.34 h60
  text ".plot_File_Name" at 577,-1064.34 h60
  text "GENERATED    :" at 2250,-1064.34 h60
  text ".Print_Date" at 3119.5,-1064.34 h60
  text ".Print_Time" at 3848.5,-1064.34 h60
  text "TEXAS INSTRUMENTS" at 5113,-1064.34 h60
M12 Stackup:
  drawing of 269 lines, arcs and shapes, not listed
  text "Layer" at 9465,7585 h60
  text "Name" at 9874.91,7585 h60
  text "Material" at 10814.65,7585 h60
  text "Thickness" at 11674.42,7585 h60
  text "Constant" at 12324.26,7585 h60
  text "Board Layer Stack" at 12894.12,7585 h60
  text "1" at 9465,7465 h60
  text "Top Overlay" at 9874.91,7465 h60
  text "2" at 9465,7345 h60
  text "Top Solder" at 9874.91,7345 h60
  text "Solder Resist" at 10814.65,7345 h60
  text "0.40mil" at 11674.42,7345 h60
  text "3.5" at 12324.26,7345 h60
  text "3" at 9465,7225 h60
  text "Top Layer" at 9874.91,7225 h60
  text "Copper" at 10814.65,7225 h60
  text "2.80mil" at 11674.42,7225 h60
  text "4" at 9465,7105 h60
  text "Dielectric1" at 9874.91,7105 h60
  text "FR-4 High Tg" at 10814.65,7105 h60
  text "8.00mil" at 11674.42,7105 h60
  text "4.8" at 12324.26,7105 h60
  text "5" at 9465,6985 h60
  text "Signal Layer 1" at 9874.91,6985 h60
  text "Copper" at 10814.65,6985 h60
  text "2.80mil" at 11674.42,6985 h60
  text "6" at 9465,6865 h60
  text "Dielectric2" at 9874.91,6865 h60
  text "FR-4 High Tg" at 10814.65,6865 h60
  text "32.00mil" at 11674.42,6865 h60
  text "4.8" at 12324.26,6865 h60
  text "7" at 9465,6745 h60
  text "Signal Layer 2" at 9874.91,6745 h60
  text "Copper" at 10814.65,6745 h60
  text "2.80mil" at 11674.42,6745 h60
  text "8" at 9465,6625 h60
  text "Dielectric3" at 9874.91,6625 h60
  text "FR-4 High Tg" at 10814.65,6625 h60
  text "10.00mil" at 11674.42,6625 h60
  text "4.8" at 12324.26,6625 h60
  text "9" at 9465,6505 h60
  text "Bottom Layer" at 9874.91,6505 h60
  text "Copper" at 10814.65,6505 h60
  text "2.80mil" at 11674.42,6505 h60
  text "10" at 9465,6385 h60
  text "Bottom Solder" at 9874.91,6385 h60
  text "Solder Resist" at 10814.65,6385 h60
  text "0.40mil" at 11674.42,6385 h60
  text "3.5" at 12324.26,6385 h60
  text ".Layer_Name" at 577,-858.49 h60
M13 Component Bodies Top:
  text ".Layer_Name" at 577,-858.49 h60
M14 Component Bodies Bottom:
  text ".Layer_Name" at 577,-858.49 h60
M15 Courtyards Top:
  text ".Layer_Name" at 577,-858.49 h60
M16 Courtyards Bottom:
  text ".Layer_Name" at 577,-858.49 h60
Drill Drawing:
  circle w1: c5735.41,3625.58 r25
  lines w1: 0,7000 0.03,7000 ; 5000,0 5000.03,0 ; 0,0 0.03,0 ; 0,0 0.03,0 ; 0,0 0.03,0 ; 0,0 0.03,0 ; 200,200 200.03,200 200,200 ; 5710.41,3750.58 5735.41,3763.08 5760.41,3750.58 5747.91,3775.58 5760.41,3800.58 5735.41,3788.08 5710.41,3800.58 5722.91,3775.58 5710.41,3750.58 ; 5710.41,3900.58 5710.41,3913.08 5722.91,3925.58 5710.41,3938.08 5710.41,3950.58 5722.91,3950.58 5735.41,3938.08 5747.91,3950.58 5760.41,3950.58 5760.41,3938.08 5747.91,3925.58 5760.41,3913.08 5760.41,3900.58 5747.91,3900.58 5735.41,3913.08 5722.91,3900.58 5710.41,3900.58 ; 5710.41,4063.08 5722.91,4063.08 5735.41,4050.58 5747.91,4063.08 5760.41,4063.08 5747.91,4075.58 5760.41,4088.08 5747.91,4088.08 5735.41,4100.58 5722.91,4088.08 5710.41,4088.08 5722.91,4075.58 5710.41,4063.08 ; 5710.41,4200.58 5760.41,4200.58 5760.41,4250.58 5710.41,4250.58 5710.41,4200.58 ; 5710.41,4375.58 5735.41,4350.58 5760.41,4375.58 5735.41,4400.58 5710.41,4375.58 ; 5710.41,4513.08 5722.91,4513.08 5722.91,4500.58 5747.91,4500.58 5747.91,4513.08 5760.41,4513.08 5760.41,4538.08 5747.91,4538.08 5747.91,4550.58 5722.91,4550.58 5722.91,4538.08 5710.41,4538.08 5710.41,4513.08 ; 5710.41,4650.58 5760.41,4650.58 5760.41,4700.58 5710.41,4700.58 5710.41,4650.58 ; 5720.41,4660.58 5750.41,4660.58 5750.41,4690.58 5720.41,4690.58 5720.41,4660.58
  lines w15: 5642.29,3555.58 9521.26,3555.58 ; 5642.29,4755.58 9521.26,4755.58 ; 6193.17,3405.58 6193.17,4905.58 ; 6890.98,3405.58 6890.98,4905.58 ; 8236.58,3405.58 8236.58,4905.58 ; 8742.46,3405.58 8742.46,4905.58 ; 5642.29,3405.58 9521.26,3405.58 9521.26,4905.58 5642.29,4905.58 5642.29,3405.58
  text "Symbol" at 5732.29,4800.58 h72
  text "Hit Count" at 6238.17,4800.58 h72
  text "Finished Hole Size" at 6935.98,4800.58 h72
  text "Plated" at 8281.58,4800.58 h72
  text "Hole Type" at 8787.46,4800.58 h72
  text "2" at 6238.17,4650.58 h60
  text "33.46mil (0.850mm)" at 6935.98,4650.58 h60
  text "PTH" at 8281.58,4650.58 h60
  text "Round" at 8787.46,4650.58 h60
  text "3" at 6238.17,4500.58 h60
  text "10.00mil (0.254mm)" at 6935.98,4500.58 h60
  text "PTH" at 8281.58,4500.58 h60
  text "Round" at 8787.46,4500.58 h60
  text "4" at 6238.17,4350.58 h60
  text "185.04mil (4.700mm)" at 6935.98,4350.58 h60
  text "NPTH" at 8281.58,4350.58 h60
  text "Round" at 8787.46,4350.58 h60
  text "10" at 6238.17,4200.58 h60
  text "68.90mil (1.750mm)" at 6935.98,4200.58 h60
  text "PTH" at 8281.58,4200.58 h60
  text "Round" at 8787.46,4200.58 h60
  text "21" at 6238.17,4050.58 h60
  text "51.18mil (1.300mm)" at 6935.98,4050.58 h60
  text "PTH" at 8281.58,4050.58 h60
  text "Round" at 8787.46,4050.58 h60
  text "75" at 6238.17,3900.58 h60
  text "7.87mil (0.200mm)" at 6935.98,3900.58 h60
  text "PTH" at 8281.58,3900.58 h60
  text "Round" at 8787.46,3900.58 h60
  text "97" at 6238.17,3750.58 h60
  text "40.00mil (1.016mm)" at 6935.98,3750.58 h60
  text "PTH" at 8281.58,3750.58 h60
  text "Round" at 8787.46,3750.58 h60
  text "607" at 6238.17,3600.58 h60
  text "12.00mil (0.305mm)" at 6935.98,3600.58 h60
  text "PTH" at 8281.58,3600.58 h60
  text "Round" at 8787.46,3600.58 h60
  text "819 Total" at 6238.17,3450.58 h60
  text ".Layer_Name" at 577,-858.49 h60

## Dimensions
0,0 to 5000,0 on M2 Board Dimensions
0,0 to 0,7000 on M2 Board Dimensions
0,-400 to 1000,-400 on M2 Board Dimensions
